VERSION 5.8 ;
BUSBITCHARS "[]" ;
DIVIDERCHAR "/" ;
UNITS
    DATABASE MICRONS 1000 ;
END UNITS

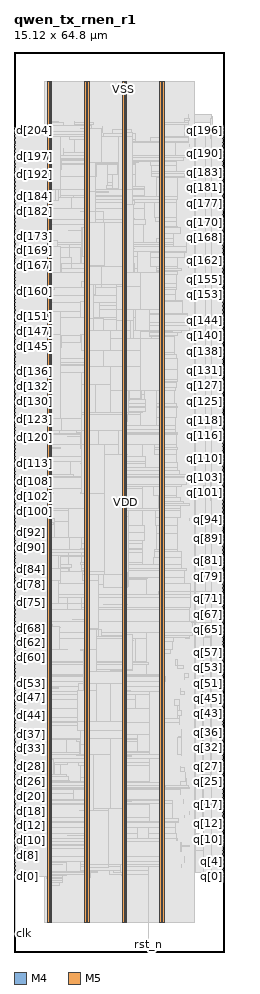
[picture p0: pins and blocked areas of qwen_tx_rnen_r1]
MACRO qwen_tx_rnen_r1
  FOREIGN qwen_tx_rnen_r1 0 0 ;
  CLASS BLOCK ;
  SIZE 15.12 BY 64.8 ;
  PIN clk
    DIRECTION INPUT ;
    USE SIGNAL ;
    PORT
      LAYER M4 ;
        RECT  0.054 1.296 0.138 1.32 ;
    END
    PORT
      LAYER M4 ;
        RECT  0.108 1.296 0.227 1.416 ;
    END
  END clk
  PIN d[0]
    DIRECTION INPUT ;
    USE SIGNAL ;
    PORT
      LAYER M4 ;
        RECT  0.054 5.424 0.138 5.448 ;
    END
  END d[0]
  PIN d[100]
    DIRECTION INPUT ;
    USE SIGNAL ;
    PORT
      LAYER M4 ;
        RECT  0.054 31.728 0.138 31.752 ;
    END
  END d[100]
  PIN d[101]
    DIRECTION INPUT ;
    USE SIGNAL ;
    PORT
      LAYER M4 ;
        RECT  0.054 32.016 0.138 32.04 ;
    END
  END d[101]
  PIN d[102]
    DIRECTION INPUT ;
    USE SIGNAL ;
    PORT
      LAYER M4 ;
        RECT  0.054 32.256 0.138 32.28 ;
    END
  END d[102]
  PIN d[103]
    DIRECTION INPUT ;
    USE SIGNAL ;
    PORT
      LAYER M4 ;
        RECT  0.054 32.496 0.138 32.52 ;
    END
  END d[103]
  PIN d[104]
    DIRECTION INPUT ;
    USE SIGNAL ;
    PORT
      LAYER M4 ;
        RECT  0.054 32.784 0.138 32.808 ;
    END
  END d[104]
  PIN d[105]
    DIRECTION INPUT ;
    USE SIGNAL ;
    PORT
      LAYER M4 ;
        RECT  0.054 33.024 0.138 33.048 ;
    END
  END d[105]
  PIN d[106]
    DIRECTION INPUT ;
    USE SIGNAL ;
    PORT
      LAYER M4 ;
        RECT  0.054 33.312 0.138 33.336 ;
    END
  END d[106]
  PIN d[107]
    DIRECTION INPUT ;
    USE SIGNAL ;
    PORT
      LAYER M4 ;
        RECT  0.054 33.552 0.138 33.576 ;
    END
  END d[107]
  PIN d[108]
    DIRECTION INPUT ;
    USE SIGNAL ;
    PORT
      LAYER M4 ;
        RECT  0.054 33.84 0.138 33.864 ;
    END
  END d[108]
  PIN d[109]
    DIRECTION INPUT ;
    USE SIGNAL ;
    PORT
      LAYER M4 ;
        RECT  0.054 34.08 0.138 34.104 ;
    END
  END d[109]
  PIN d[10]
    DIRECTION INPUT ;
    USE SIGNAL ;
    PORT
      LAYER M4 ;
        RECT  0.054 8.016 0.138 8.04 ;
    END
  END d[10]
  PIN d[110]
    DIRECTION INPUT ;
    USE SIGNAL ;
    PORT
      LAYER M4 ;
        RECT  0.054 34.368 0.138 34.392 ;
    END
  END d[110]
  PIN d[111]
    DIRECTION INPUT ;
    USE SIGNAL ;
    PORT
      LAYER M4 ;
        RECT  0.054 34.608 0.138 34.632 ;
    END
  END d[111]
  PIN d[112]
    DIRECTION INPUT ;
    USE SIGNAL ;
    PORT
      LAYER M4 ;
        RECT  0.054 34.896 0.138 34.92 ;
    END
  END d[112]
  PIN d[113]
    DIRECTION INPUT ;
    USE SIGNAL ;
    PORT
      LAYER M4 ;
        RECT  0.054 35.136 0.138 35.16 ;
    END
  END d[113]
  PIN d[114]
    DIRECTION INPUT ;
    USE SIGNAL ;
    PORT
      LAYER M4 ;
        RECT  0.054 35.424 0.138 35.448 ;
    END
  END d[114]
  PIN d[115]
    DIRECTION INPUT ;
    USE SIGNAL ;
    PORT
      LAYER M4 ;
        RECT  0.054 35.664 0.138 35.688 ;
    END
  END d[115]
  PIN d[116]
    DIRECTION INPUT ;
    USE SIGNAL ;
    PORT
      LAYER M4 ;
        RECT  0.054 35.952 0.138 35.976 ;
    END
  END d[116]
  PIN d[117]
    DIRECTION INPUT ;
    USE SIGNAL ;
    PORT
      LAYER M4 ;
        RECT  0.054 36.192 0.138 36.216 ;
    END
  END d[117]
  PIN d[118]
    DIRECTION INPUT ;
    USE SIGNAL ;
    PORT
      LAYER M4 ;
        RECT  0.054 36.48 0.138 36.504 ;
    END
  END d[118]
  PIN d[119]
    DIRECTION INPUT ;
    USE SIGNAL ;
    PORT
      LAYER M4 ;
        RECT  0.054 36.72 0.138 36.744 ;
    END
  END d[119]
  PIN d[11]
    DIRECTION INPUT ;
    USE SIGNAL ;
    PORT
      LAYER M4 ;
        RECT  0.054 8.304 0.138 8.328 ;
    END
  END d[11]
  PIN d[120]
    DIRECTION INPUT ;
    USE SIGNAL ;
    PORT
      LAYER M4 ;
        RECT  0.054 37.008 0.138 37.032 ;
    END
  END d[120]
  PIN d[121]
    DIRECTION INPUT ;
    USE SIGNAL ;
    PORT
      LAYER M4 ;
        RECT  0.054 37.248 0.138 37.272 ;
    END
  END d[121]
  PIN d[122]
    DIRECTION INPUT ;
    USE SIGNAL ;
    PORT
      LAYER M4 ;
        RECT  0.054 37.536 0.138 37.56 ;
    END
  END d[122]
  PIN d[123]
    DIRECTION INPUT ;
    USE SIGNAL ;
    PORT
      LAYER M4 ;
        RECT  0.054 37.776 0.138 37.8 ;
    END
  END d[123]
  PIN d[124]
    DIRECTION INPUT ;
    USE SIGNAL ;
    PORT
      LAYER M4 ;
        RECT  0.054 38.064 0.138 38.088 ;
    END
  END d[124]
  PIN d[125]
    DIRECTION INPUT ;
    USE SIGNAL ;
    PORT
      LAYER M4 ;
        RECT  0.054 38.304 0.138 38.328 ;
    END
  END d[125]
  PIN d[126]
    DIRECTION INPUT ;
    USE SIGNAL ;
    PORT
      LAYER M4 ;
        RECT  0.054 38.592 0.138 38.616 ;
    END
  END d[126]
  PIN d[127]
    DIRECTION INPUT ;
    USE SIGNAL ;
    PORT
      LAYER M4 ;
        RECT  0.054 38.832 0.138 38.856 ;
    END
  END d[127]
  PIN d[128]
    DIRECTION INPUT ;
    USE SIGNAL ;
    PORT
      LAYER M4 ;
        RECT  0.054 39.12 0.138 39.144 ;
    END
  END d[128]
  PIN d[129]
    DIRECTION INPUT ;
    USE SIGNAL ;
    PORT
      LAYER M4 ;
        RECT  0.054 39.36 0.138 39.384 ;
    END
  END d[129]
  PIN d[12]
    DIRECTION INPUT ;
    USE SIGNAL ;
    PORT
      LAYER M4 ;
        RECT  0.054 8.544 0.138 8.568 ;
    END
  END d[12]
  PIN d[130]
    DIRECTION INPUT ;
    USE SIGNAL ;
    PORT
      LAYER M4 ;
        RECT  0.054 39.648 0.138 39.672 ;
    END
  END d[130]
  PIN d[131]
    DIRECTION INPUT ;
    USE SIGNAL ;
    PORT
      LAYER M4 ;
        RECT  0.054 39.888 0.138 39.912 ;
    END
  END d[131]
  PIN d[132]
    DIRECTION INPUT ;
    USE SIGNAL ;
    PORT
      LAYER M4 ;
        RECT  0.054 40.176 0.138 40.2 ;
    END
  END d[132]
  PIN d[133]
    DIRECTION INPUT ;
    USE SIGNAL ;
    PORT
      LAYER M4 ;
        RECT  0.054 40.416 0.138 40.44 ;
    END
  END d[133]
  PIN d[134]
    DIRECTION INPUT ;
    USE SIGNAL ;
    PORT
      LAYER M4 ;
        RECT  0.054 40.704 0.138 40.728 ;
    END
  END d[134]
  PIN d[135]
    DIRECTION INPUT ;
    USE SIGNAL ;
    PORT
      LAYER M4 ;
        RECT  0.054 40.944 0.138 40.968 ;
    END
  END d[135]
  PIN d[136]
    DIRECTION INPUT ;
    USE SIGNAL ;
    PORT
      LAYER M4 ;
        RECT  0.054 41.232 0.138 41.256 ;
    END
  END d[136]
  PIN d[137]
    DIRECTION INPUT ;
    USE SIGNAL ;
    PORT
      LAYER M4 ;
        RECT  0.054 41.472 0.138 41.496 ;
    END
  END d[137]
  PIN d[138]
    DIRECTION INPUT ;
    USE SIGNAL ;
    PORT
      LAYER M4 ;
        RECT  0.054 41.76 0.138 41.784 ;
    END
  END d[138]
  PIN d[139]
    DIRECTION INPUT ;
    USE SIGNAL ;
    PORT
      LAYER M4 ;
        RECT  0.054 42 0.138 42.024 ;
    END
  END d[139]
  PIN d[13]
    DIRECTION INPUT ;
    USE SIGNAL ;
    PORT
      LAYER M4 ;
        RECT  0.054 8.832 0.138 8.856 ;
    END
  END d[13]
  PIN d[140]
    DIRECTION INPUT ;
    USE SIGNAL ;
    PORT
      LAYER M4 ;
        RECT  0.054 42.288 0.138 42.312 ;
    END
  END d[140]
  PIN d[141]
    DIRECTION INPUT ;
    USE SIGNAL ;
    PORT
      LAYER M4 ;
        RECT  0.054 42.528 0.138 42.552 ;
    END
  END d[141]
  PIN d[142]
    DIRECTION INPUT ;
    USE SIGNAL ;
    PORT
      LAYER M4 ;
        RECT  0.054 42.816 0.138 42.84 ;
    END
  END d[142]
  PIN d[143]
    DIRECTION INPUT ;
    USE SIGNAL ;
    PORT
      LAYER M4 ;
        RECT  0.054 43.056 0.138 43.08 ;
    END
  END d[143]
  PIN d[144]
    DIRECTION INPUT ;
    USE SIGNAL ;
    PORT
      LAYER M4 ;
        RECT  0.054 43.296 0.138 43.32 ;
    END
  END d[144]
  PIN d[145]
    DIRECTION INPUT ;
    USE SIGNAL ;
    PORT
      LAYER M4 ;
        RECT  0.054 43.584 0.138 43.608 ;
    END
  END d[145]
  PIN d[146]
    DIRECTION INPUT ;
    USE SIGNAL ;
    PORT
      LAYER M4 ;
        RECT  0.054 43.824 0.138 43.848 ;
    END
  END d[146]
  PIN d[147]
    DIRECTION INPUT ;
    USE SIGNAL ;
    PORT
      LAYER M4 ;
        RECT  0.054 44.112 0.138 44.136 ;
    END
  END d[147]
  PIN d[148]
    DIRECTION INPUT ;
    USE SIGNAL ;
    PORT
      LAYER M4 ;
        RECT  0.054 44.352 0.138 44.376 ;
    END
  END d[148]
  PIN d[149]
    DIRECTION INPUT ;
    USE SIGNAL ;
    PORT
      LAYER M4 ;
        RECT  0.054 44.64 0.138 44.664 ;
    END
  END d[149]
  PIN d[14]
    DIRECTION INPUT ;
    USE SIGNAL ;
    PORT
      LAYER M4 ;
        RECT  0.054 9.072 0.138 9.096 ;
    END
  END d[14]
  PIN d[150]
    DIRECTION INPUT ;
    USE SIGNAL ;
    PORT
      LAYER M4 ;
        RECT  0.054 44.88 0.138 44.904 ;
    END
  END d[150]
  PIN d[151]
    DIRECTION INPUT ;
    USE SIGNAL ;
    PORT
      LAYER M4 ;
        RECT  0.054 45.168 0.138 45.192 ;
    END
  END d[151]
  PIN d[152]
    DIRECTION INPUT ;
    USE SIGNAL ;
    PORT
      LAYER M4 ;
        RECT  0.054 45.408 0.138 45.432 ;
    END
  END d[152]
  PIN d[153]
    DIRECTION INPUT ;
    USE SIGNAL ;
    PORT
      LAYER M4 ;
        RECT  0.054 45.696 0.138 45.72 ;
    END
  END d[153]
  PIN d[154]
    DIRECTION INPUT ;
    USE SIGNAL ;
    PORT
      LAYER M4 ;
        RECT  0.054 45.936 0.138 45.96 ;
    END
  END d[154]
  PIN d[155]
    DIRECTION INPUT ;
    USE SIGNAL ;
    PORT
      LAYER M4 ;
        RECT  0.054 46.224 0.138 46.248 ;
    END
  END d[155]
  PIN d[156]
    DIRECTION INPUT ;
    USE SIGNAL ;
    PORT
      LAYER M4 ;
        RECT  0.054 46.464 0.138 46.488 ;
    END
  END d[156]
  PIN d[157]
    DIRECTION INPUT ;
    USE SIGNAL ;
    PORT
      LAYER M4 ;
        RECT  0.054 46.752 0.138 46.776 ;
    END
  END d[157]
  PIN d[158]
    DIRECTION INPUT ;
    USE SIGNAL ;
    PORT
      LAYER M4 ;
        RECT  0.054 46.992 0.138 47.016 ;
    END
  END d[158]
  PIN d[159]
    DIRECTION INPUT ;
    USE SIGNAL ;
    PORT
      LAYER M4 ;
        RECT  0.054 47.28 0.138 47.304 ;
    END
  END d[159]
  PIN d[15]
    DIRECTION INPUT ;
    USE SIGNAL ;
    PORT
      LAYER M4 ;
        RECT  0.054 9.36 0.138 9.384 ;
    END
  END d[15]
  PIN d[160]
    DIRECTION INPUT ;
    USE SIGNAL ;
    PORT
      LAYER M4 ;
        RECT  0.054 47.52 0.138 47.544 ;
    END
  END d[160]
  PIN d[161]
    DIRECTION INPUT ;
    USE SIGNAL ;
    PORT
      LAYER M4 ;
        RECT  0.054 47.808 0.138 47.832 ;
    END
  END d[161]
  PIN d[162]
    DIRECTION INPUT ;
    USE SIGNAL ;
    PORT
      LAYER M4 ;
        RECT  0.054 48.048 0.138 48.072 ;
    END
  END d[162]
  PIN d[163]
    DIRECTION INPUT ;
    USE SIGNAL ;
    PORT
      LAYER M4 ;
        RECT  0.054 48.336 0.138 48.36 ;
    END
  END d[163]
  PIN d[164]
    DIRECTION INPUT ;
    USE SIGNAL ;
    PORT
      LAYER M4 ;
        RECT  0.054 48.576 0.138 48.6 ;
    END
  END d[164]
  PIN d[165]
    DIRECTION INPUT ;
    USE SIGNAL ;
    PORT
      LAYER M4 ;
        RECT  0.054 48.864 0.138 48.888 ;
    END
  END d[165]
  PIN d[166]
    DIRECTION INPUT ;
    USE SIGNAL ;
    PORT
      LAYER M4 ;
        RECT  0.054 49.104 0.138 49.128 ;
    END
  END d[166]
  PIN d[167]
    DIRECTION INPUT ;
    USE SIGNAL ;
    PORT
      LAYER M4 ;
        RECT  0.054 49.392 0.138 49.416 ;
    END
  END d[167]
  PIN d[168]
    DIRECTION INPUT ;
    USE SIGNAL ;
    PORT
      LAYER M4 ;
        RECT  0.054 49.632 0.138 49.656 ;
    END
  END d[168]
  PIN d[169]
    DIRECTION INPUT ;
    USE SIGNAL ;
    PORT
      LAYER M4 ;
        RECT  0.054 49.92 0.138 49.944 ;
    END
  END d[169]
  PIN d[16]
    DIRECTION INPUT ;
    USE SIGNAL ;
    PORT
      LAYER M4 ;
        RECT  0.054 9.6 0.138 9.624 ;
    END
  END d[16]
  PIN d[170]
    DIRECTION INPUT ;
    USE SIGNAL ;
    PORT
      LAYER M4 ;
        RECT  0.054 50.16 0.138 50.184 ;
    END
  END d[170]
  PIN d[171]
    DIRECTION INPUT ;
    USE SIGNAL ;
    PORT
      LAYER M4 ;
        RECT  0.054 50.448 0.138 50.472 ;
    END
  END d[171]
  PIN d[172]
    DIRECTION INPUT ;
    USE SIGNAL ;
    PORT
      LAYER M4 ;
        RECT  0.054 50.688 0.138 50.712 ;
    END
  END d[172]
  PIN d[173]
    DIRECTION INPUT ;
    USE SIGNAL ;
    PORT
      LAYER M4 ;
        RECT  0.054 50.976 0.138 51 ;
    END
  END d[173]
  PIN d[174]
    DIRECTION INPUT ;
    USE SIGNAL ;
    PORT
      LAYER M4 ;
        RECT  0.054 51.216 0.138 51.24 ;
    END
  END d[174]
  PIN d[175]
    DIRECTION INPUT ;
    USE SIGNAL ;
    PORT
      LAYER M4 ;
        RECT  0.054 51.504 0.138 51.528 ;
    END
  END d[175]
  PIN d[176]
    DIRECTION INPUT ;
    USE SIGNAL ;
    PORT
      LAYER M4 ;
        RECT  0.054 51.744 0.138 51.768 ;
    END
  END d[176]
  PIN d[177]
    DIRECTION INPUT ;
    USE SIGNAL ;
    PORT
      LAYER M4 ;
        RECT  0.054 52.032 0.138 52.056 ;
    END
  END d[177]
  PIN d[178]
    DIRECTION INPUT ;
    USE SIGNAL ;
    PORT
      LAYER M4 ;
        RECT  0.054 52.272 0.138 52.296 ;
    END
  END d[178]
  PIN d[179]
    DIRECTION INPUT ;
    USE SIGNAL ;
    PORT
      LAYER M4 ;
        RECT  0.054 52.56 0.138 52.584 ;
    END
  END d[179]
  PIN d[17]
    DIRECTION INPUT ;
    USE SIGNAL ;
    PORT
      LAYER M4 ;
        RECT  0.054 9.888 0.138 9.912 ;
    END
  END d[17]
  PIN d[180]
    DIRECTION INPUT ;
    USE SIGNAL ;
    PORT
      LAYER M4 ;
        RECT  0.054 52.8 0.138 52.824 ;
    END
  END d[180]
  PIN d[181]
    DIRECTION INPUT ;
    USE SIGNAL ;
    PORT
      LAYER M4 ;
        RECT  0.054 53.088 0.138 53.112 ;
    END
  END d[181]
  PIN d[182]
    DIRECTION INPUT ;
    USE SIGNAL ;
    PORT
      LAYER M4 ;
        RECT  0.054 53.328 0.138 53.352 ;
    END
  END d[182]
  PIN d[183]
    DIRECTION INPUT ;
    USE SIGNAL ;
    PORT
      LAYER M4 ;
        RECT  0.054 53.616 0.138 53.64 ;
    END
  END d[183]
  PIN d[184]
    DIRECTION INPUT ;
    USE SIGNAL ;
    PORT
      LAYER M4 ;
        RECT  0.054 53.856 0.138 53.88 ;
    END
  END d[184]
  PIN d[185]
    DIRECTION INPUT ;
    USE SIGNAL ;
    PORT
      LAYER M4 ;
        RECT  0.054 54.096 0.138 54.12 ;
    END
  END d[185]
  PIN d[186]
    DIRECTION INPUT ;
    USE SIGNAL ;
    PORT
      LAYER M4 ;
        RECT  0.054 54.384 0.138 54.408 ;
    END
  END d[186]
  PIN d[187]
    DIRECTION INPUT ;
    USE SIGNAL ;
    PORT
      LAYER M4 ;
        RECT  0.054 54.624 0.138 54.648 ;
    END
  END d[187]
  PIN d[188]
    DIRECTION INPUT ;
    USE SIGNAL ;
    PORT
      LAYER M4 ;
        RECT  0.054 54.912 0.138 54.936 ;
    END
  END d[188]
  PIN d[189]
    DIRECTION INPUT ;
    USE SIGNAL ;
    PORT
      LAYER M4 ;
        RECT  0.054 55.152 0.138 55.176 ;
    END
  END d[189]
  PIN d[18]
    DIRECTION INPUT ;
    USE SIGNAL ;
    PORT
      LAYER M4 ;
        RECT  0.054 10.128 0.138 10.152 ;
    END
  END d[18]
  PIN d[190]
    DIRECTION INPUT ;
    USE SIGNAL ;
    PORT
      LAYER M4 ;
        RECT  0.054 55.44 0.138 55.464 ;
    END
  END d[190]
  PIN d[191]
    DIRECTION INPUT ;
    USE SIGNAL ;
    PORT
      LAYER M4 ;
        RECT  0.054 55.68 0.138 55.704 ;
    END
  END d[191]
  PIN d[192]
    DIRECTION INPUT ;
    USE SIGNAL ;
    PORT
      LAYER M4 ;
        RECT  0.054 55.968 0.138 55.992 ;
    END
  END d[192]
  PIN d[193]
    DIRECTION INPUT ;
    USE SIGNAL ;
    PORT
      LAYER M4 ;
        RECT  0.054 56.208 0.138 56.232 ;
    END
  END d[193]
  PIN d[194]
    DIRECTION INPUT ;
    USE SIGNAL ;
    PORT
      LAYER M4 ;
        RECT  0.054 56.496 0.138 56.52 ;
    END
  END d[194]
  PIN d[195]
    DIRECTION INPUT ;
    USE SIGNAL ;
    PORT
      LAYER M4 ;
        RECT  0.054 56.736 0.138 56.76 ;
    END
  END d[195]
  PIN d[196]
    DIRECTION INPUT ;
    USE SIGNAL ;
    PORT
      LAYER M4 ;
        RECT  0.054 57.024 0.138 57.048 ;
    END
  END d[196]
  PIN d[197]
    DIRECTION INPUT ;
    USE SIGNAL ;
    PORT
      LAYER M4 ;
        RECT  0.054 57.264 0.138 57.288 ;
    END
  END d[197]
  PIN d[198]
    DIRECTION INPUT ;
    USE SIGNAL ;
    PORT
      LAYER M4 ;
        RECT  0.054 57.552 0.138 57.576 ;
    END
  END d[198]
  PIN d[199]
    DIRECTION INPUT ;
    USE SIGNAL ;
    PORT
      LAYER M4 ;
        RECT  0.054 57.792 0.138 57.816 ;
    END
  END d[199]
  PIN d[19]
    DIRECTION INPUT ;
    USE SIGNAL ;
    PORT
      LAYER M4 ;
        RECT  0.054 10.416 0.138 10.44 ;
    END
  END d[19]
  PIN d[1]
    DIRECTION INPUT ;
    USE SIGNAL ;
    PORT
      LAYER M4 ;
        RECT  0.054 5.664 0.138 5.688 ;
    END
  END d[1]
  PIN d[200]
    DIRECTION INPUT ;
    USE SIGNAL ;
    PORT
      LAYER M4 ;
        RECT  0.054 58.08 0.138 58.104 ;
    END
  END d[200]
  PIN d[201]
    DIRECTION INPUT ;
    USE SIGNAL ;
    PORT
      LAYER M4 ;
        RECT  0.054 58.32 0.138 58.344 ;
    END
    PORT
      LAYER M4 ;
        RECT  0.025 58.224 0.108 58.344 ;
    END
  END d[201]
  PIN d[202]
    DIRECTION INPUT ;
    USE SIGNAL ;
    PORT
      LAYER M4 ;
        RECT  0.054 58.608 0.138 58.632 ;
    END
  END d[202]
  PIN d[203]
    DIRECTION INPUT ;
    USE SIGNAL ;
    PORT
      LAYER M4 ;
        RECT  0.054 58.848 0.138 58.872 ;
    END
  END d[203]
  PIN d[204]
    DIRECTION INPUT ;
    USE SIGNAL ;
    PORT
      LAYER M4 ;
        RECT  0.054 59.136 0.138 59.16 ;
    END
  END d[204]
  PIN d[205]
    DIRECTION INPUT ;
    USE SIGNAL ;
    PORT
      LAYER M4 ;
        RECT  0.054 59.376 0.138 59.4 ;
    END
  END d[205]
  PIN d[20]
    DIRECTION INPUT ;
    USE SIGNAL ;
    PORT
      LAYER M4 ;
        RECT  0.054 10.656 0.138 10.68 ;
    END
  END d[20]
  PIN d[21]
    DIRECTION INPUT ;
    USE SIGNAL ;
    PORT
      LAYER M4 ;
        RECT  0.054 10.896 0.138 10.92 ;
    END
  END d[21]
  PIN d[22]
    DIRECTION INPUT ;
    USE SIGNAL ;
    PORT
      LAYER M4 ;
        RECT  0.054 11.184 0.138 11.208 ;
    END
  END d[22]
  PIN d[23]
    DIRECTION INPUT ;
    USE SIGNAL ;
    PORT
      LAYER M4 ;
        RECT  0.054 11.424 0.138 11.448 ;
    END
  END d[23]
  PIN d[24]
    DIRECTION INPUT ;
    USE SIGNAL ;
    PORT
      LAYER M4 ;
        RECT  0.054 11.712 0.138 11.736 ;
    END
  END d[24]
  PIN d[25]
    DIRECTION INPUT ;
    USE SIGNAL ;
    PORT
      LAYER M4 ;
        RECT  0.054 11.952 0.138 11.976 ;
    END
  END d[25]
  PIN d[26]
    DIRECTION INPUT ;
    USE SIGNAL ;
    PORT
      LAYER M4 ;
        RECT  0.054 12.24 0.138 12.264 ;
    END
  END d[26]
  PIN d[27]
    DIRECTION INPUT ;
    USE SIGNAL ;
    PORT
      LAYER M4 ;
        RECT  0.054 12.48 0.138 12.504 ;
    END
  END d[27]
  PIN d[28]
    DIRECTION INPUT ;
    USE SIGNAL ;
    PORT
      LAYER M4 ;
        RECT  0.054 12.768 0.138 12.792 ;
    END
  END d[28]
  PIN d[29]
    DIRECTION INPUT ;
    USE SIGNAL ;
    PORT
      LAYER M4 ;
        RECT  0.054 13.008 0.138 13.032 ;
    END
  END d[29]
  PIN d[2]
    DIRECTION INPUT ;
    USE SIGNAL ;
    PORT
      LAYER M4 ;
        RECT  0.054 5.904 0.138 5.928 ;
    END
  END d[2]
  PIN d[30]
    DIRECTION INPUT ;
    USE SIGNAL ;
    PORT
      LAYER M4 ;
        RECT  0.054 13.296 0.138 13.32 ;
    END
  END d[30]
  PIN d[31]
    DIRECTION INPUT ;
    USE SIGNAL ;
    PORT
      LAYER M4 ;
        RECT  0.054 13.536 0.138 13.56 ;
    END
  END d[31]
  PIN d[32]
    DIRECTION INPUT ;
    USE SIGNAL ;
    PORT
      LAYER M4 ;
        RECT  0.054 13.824 0.138 13.848 ;
    END
  END d[32]
  PIN d[33]
    DIRECTION INPUT ;
    USE SIGNAL ;
    PORT
      LAYER M4 ;
        RECT  0.054 14.064 0.138 14.088 ;
    END
  END d[33]
  PIN d[34]
    DIRECTION INPUT ;
    USE SIGNAL ;
    PORT
      LAYER M4 ;
        RECT  0.054 14.352 0.138 14.376 ;
    END
  END d[34]
  PIN d[35]
    DIRECTION INPUT ;
    USE SIGNAL ;
    PORT
      LAYER M4 ;
        RECT  0.054 14.592 0.138 14.616 ;
    END
  END d[35]
  PIN d[36]
    DIRECTION INPUT ;
    USE SIGNAL ;
    PORT
      LAYER M4 ;
        RECT  0.054 14.88 0.138 14.904 ;
    END
  END d[36]
  PIN d[37]
    DIRECTION INPUT ;
    USE SIGNAL ;
    PORT
      LAYER M4 ;
        RECT  0.054 15.12 0.138 15.144 ;
    END
  END d[37]
  PIN d[38]
    DIRECTION INPUT ;
    USE SIGNAL ;
    PORT
      LAYER M4 ;
        RECT  0.054 15.408 0.138 15.432 ;
    END
  END d[38]
  PIN d[39]
    DIRECTION INPUT ;
    USE SIGNAL ;
    PORT
      LAYER M4 ;
        RECT  0.054 15.648 0.138 15.672 ;
    END
  END d[39]
  PIN d[3]
    DIRECTION INPUT ;
    USE SIGNAL ;
    PORT
      LAYER M4 ;
        RECT  0.054 6.192 0.138 6.216 ;
    END
  END d[3]
  PIN d[40]
    DIRECTION INPUT ;
    USE SIGNAL ;
    PORT
      LAYER M4 ;
        RECT  0.054 15.936 0.138 15.96 ;
    END
  END d[40]
  PIN d[41]
    DIRECTION INPUT ;
    USE SIGNAL ;
    PORT
      LAYER M4 ;
        RECT  0.054 16.176 0.138 16.2 ;
    END
  END d[41]
  PIN d[42]
    DIRECTION INPUT ;
    USE SIGNAL ;
    PORT
      LAYER M4 ;
        RECT  0.054 16.464 0.138 16.488 ;
    END
  END d[42]
  PIN d[43]
    DIRECTION INPUT ;
    USE SIGNAL ;
    PORT
      LAYER M4 ;
        RECT  0.054 16.704 0.138 16.728 ;
    END
  END d[43]
  PIN d[44]
    DIRECTION INPUT ;
    USE SIGNAL ;
    PORT
      LAYER M4 ;
        RECT  0.054 16.992 0.138 17.016 ;
    END
  END d[44]
  PIN d[45]
    DIRECTION INPUT ;
    USE SIGNAL ;
    PORT
      LAYER M4 ;
        RECT  0.054 17.232 0.138 17.256 ;
    END
  END d[45]
  PIN d[46]
    DIRECTION INPUT ;
    USE SIGNAL ;
    PORT
      LAYER M4 ;
        RECT  0.054 17.52 0.138 17.544 ;
    END
  END d[46]
  PIN d[47]
    DIRECTION INPUT ;
    USE SIGNAL ;
    PORT
      LAYER M4 ;
        RECT  0.054 17.76 0.138 17.784 ;
    END
  END d[47]
  PIN d[48]
    DIRECTION INPUT ;
    USE SIGNAL ;
    PORT
      LAYER M4 ;
        RECT  0.054 18.048 0.138 18.072 ;
    END
  END d[48]
  PIN d[49]
    DIRECTION INPUT ;
    USE SIGNAL ;
    PORT
      LAYER M4 ;
        RECT  0.054 18.288 0.138 18.312 ;
    END
  END d[49]
  PIN d[4]
    DIRECTION INPUT ;
    USE SIGNAL ;
    PORT
      LAYER M4 ;
        RECT  0.054 6.432 0.138 6.456 ;
    END
  END d[4]
  PIN d[50]
    DIRECTION INPUT ;
    USE SIGNAL ;
    PORT
      LAYER M4 ;
        RECT  0.054 18.576 0.138 18.6 ;
    END
  END d[50]
  PIN d[51]
    DIRECTION INPUT ;
    USE SIGNAL ;
    PORT
      LAYER M4 ;
        RECT  0.054 18.816 0.138 18.84 ;
    END
  END d[51]
  PIN d[52]
    DIRECTION INPUT ;
    USE SIGNAL ;
    PORT
      LAYER M4 ;
        RECT  0.054 19.104 0.138 19.128 ;
    END
  END d[52]
  PIN d[53]
    DIRECTION INPUT ;
    USE SIGNAL ;
    PORT
      LAYER M4 ;
        RECT  0.054 19.344 0.138 19.368 ;
    END
  END d[53]
  PIN d[54]
    DIRECTION INPUT ;
    USE SIGNAL ;
    PORT
      LAYER M4 ;
        RECT  0.054 19.632 0.138 19.656 ;
    END
  END d[54]
  PIN d[55]
    DIRECTION INPUT ;
    USE SIGNAL ;
    PORT
      LAYER M4 ;
        RECT  0.054 19.872 0.138 19.896 ;
    END
  END d[55]
  PIN d[56]
    DIRECTION INPUT ;
    USE SIGNAL ;
    PORT
      LAYER M4 ;
        RECT  0.054 20.16 0.138 20.184 ;
    END
  END d[56]
  PIN d[57]
    DIRECTION INPUT ;
    USE SIGNAL ;
    PORT
      LAYER M4 ;
        RECT  0.054 20.4 0.138 20.424 ;
    END
  END d[57]
  PIN d[58]
    DIRECTION INPUT ;
    USE SIGNAL ;
    PORT
      LAYER M4 ;
        RECT  0.054 20.688 0.138 20.712 ;
    END
  END d[58]
  PIN d[59]
    DIRECTION INPUT ;
    USE SIGNAL ;
    PORT
      LAYER M4 ;
        RECT  0.054 20.928 0.138 20.952 ;
    END
  END d[59]
  PIN d[5]
    DIRECTION INPUT ;
    USE SIGNAL ;
    PORT
      LAYER M4 ;
        RECT  0.054 6.72 0.138 6.744 ;
    END
  END d[5]
  PIN d[60]
    DIRECTION INPUT ;
    USE SIGNAL ;
    PORT
      LAYER M4 ;
        RECT  0.054 21.216 0.138 21.24 ;
    END
  END d[60]
  PIN d[61]
    DIRECTION INPUT ;
    USE SIGNAL ;
    PORT
      LAYER M4 ;
        RECT  0.054 21.456 0.138 21.48 ;
    END
  END d[61]
  PIN d[62]
    DIRECTION INPUT ;
    USE SIGNAL ;
    PORT
      LAYER M4 ;
        RECT  0.054 21.696 0.138 21.72 ;
    END
  END d[62]
  PIN d[63]
    DIRECTION INPUT ;
    USE SIGNAL ;
    PORT
      LAYER M4 ;
        RECT  0.054 21.984 0.138 22.008 ;
    END
  END d[63]
  PIN d[64]
    DIRECTION INPUT ;
    USE SIGNAL ;
    PORT
      LAYER M4 ;
        RECT  0.054 22.224 0.138 22.248 ;
    END
  END d[64]
  PIN d[65]
    DIRECTION INPUT ;
    USE SIGNAL ;
    PORT
      LAYER M4 ;
        RECT  0.054 22.512 0.138 22.536 ;
    END
  END d[65]
  PIN d[66]
    DIRECTION INPUT ;
    USE SIGNAL ;
    PORT
      LAYER M4 ;
        RECT  0.054 22.752 0.138 22.776 ;
    END
  END d[66]
  PIN d[67]
    DIRECTION INPUT ;
    USE SIGNAL ;
    PORT
      LAYER M4 ;
        RECT  0.054 23.04 0.138 23.064 ;
    END
  END d[67]
  PIN d[68]
    DIRECTION INPUT ;
    USE SIGNAL ;
    PORT
      LAYER M4 ;
        RECT  0.054 23.28 0.138 23.304 ;
    END
  END d[68]
  PIN d[69]
    DIRECTION INPUT ;
    USE SIGNAL ;
    PORT
      LAYER M4 ;
        RECT  0.054 23.568 0.138 23.592 ;
    END
  END d[69]
  PIN d[6]
    DIRECTION INPUT ;
    USE SIGNAL ;
    PORT
      LAYER M4 ;
        RECT  0.054 6.96 0.138 6.984 ;
    END
  END d[6]
  PIN d[70]
    DIRECTION INPUT ;
    USE SIGNAL ;
    PORT
      LAYER M4 ;
        RECT  0.054 23.808 0.138 23.832 ;
    END
  END d[70]
  PIN d[71]
    DIRECTION INPUT ;
    USE SIGNAL ;
    PORT
      LAYER M4 ;
        RECT  0.054 24.096 0.138 24.12 ;
    END
  END d[71]
  PIN d[72]
    DIRECTION INPUT ;
    USE SIGNAL ;
    PORT
      LAYER M4 ;
        RECT  0.054 24.336 0.138 24.36 ;
    END
  END d[72]
  PIN d[73]
    DIRECTION INPUT ;
    USE SIGNAL ;
    PORT
      LAYER M4 ;
        RECT  0.054 24.624 0.138 24.648 ;
    END
  END d[73]
  PIN d[74]
    DIRECTION INPUT ;
    USE SIGNAL ;
    PORT
      LAYER M4 ;
        RECT  0.054 24.864 0.138 24.888 ;
    END
  END d[74]
  PIN d[75]
    DIRECTION INPUT ;
    USE SIGNAL ;
    PORT
      LAYER M4 ;
        RECT  0.054 25.152 0.138 25.176 ;
    END
  END d[75]
  PIN d[76]
    DIRECTION INPUT ;
    USE SIGNAL ;
    PORT
      LAYER M4 ;
        RECT  0.054 25.392 0.138 25.416 ;
    END
  END d[76]
  PIN d[77]
    DIRECTION INPUT ;
    USE SIGNAL ;
    PORT
      LAYER M4 ;
        RECT  0.054 25.68 0.138 25.704 ;
    END
  END d[77]
  PIN d[78]
    DIRECTION INPUT ;
    USE SIGNAL ;
    PORT
      LAYER M4 ;
        RECT  0.054 25.92 0.138 25.944 ;
    END
  END d[78]
  PIN d[79]
    DIRECTION INPUT ;
    USE SIGNAL ;
    PORT
      LAYER M4 ;
        RECT  0.054 26.208 0.138 26.232 ;
    END
  END d[79]
  PIN d[7]
    DIRECTION INPUT ;
    USE SIGNAL ;
    PORT
      LAYER M4 ;
        RECT  0.054 7.248 0.138 7.272 ;
    END
  END d[7]
  PIN d[80]
    DIRECTION INPUT ;
    USE SIGNAL ;
    PORT
      LAYER M4 ;
        RECT  0.054 26.448 0.138 26.472 ;
    END
  END d[80]
  PIN d[81]
    DIRECTION INPUT ;
    USE SIGNAL ;
    PORT
      LAYER M4 ;
        RECT  0.054 26.736 0.138 26.76 ;
    END
  END d[81]
  PIN d[82]
    DIRECTION INPUT ;
    USE SIGNAL ;
    PORT
      LAYER M4 ;
        RECT  0.054 26.976 0.138 27 ;
    END
  END d[82]
  PIN d[83]
    DIRECTION INPUT ;
    USE SIGNAL ;
    PORT
      LAYER M4 ;
        RECT  0.054 27.264 0.138 27.288 ;
    END
  END d[83]
  PIN d[84]
    DIRECTION INPUT ;
    USE SIGNAL ;
    PORT
      LAYER M4 ;
        RECT  0.054 27.504 0.138 27.528 ;
    END
  END d[84]
  PIN d[85]
    DIRECTION INPUT ;
    USE SIGNAL ;
    PORT
      LAYER M4 ;
        RECT  0.054 27.792 0.138 27.816 ;
    END
  END d[85]
  PIN d[86]
    DIRECTION INPUT ;
    USE SIGNAL ;
    PORT
      LAYER M4 ;
        RECT  0.054 28.032 0.138 28.056 ;
    END
  END d[86]
  PIN d[87]
    DIRECTION INPUT ;
    USE SIGNAL ;
    PORT
      LAYER M4 ;
        RECT  0.054 28.32 0.138 28.344 ;
    END
  END d[87]
  PIN d[88]
    DIRECTION INPUT ;
    USE SIGNAL ;
    PORT
      LAYER M4 ;
        RECT  0.054 28.56 0.138 28.584 ;
    END
  END d[88]
  PIN d[89]
    DIRECTION INPUT ;
    USE SIGNAL ;
    PORT
      LAYER M4 ;
        RECT  0.054 28.848 0.138 28.872 ;
    END
  END d[89]
  PIN d[8]
    DIRECTION INPUT ;
    USE SIGNAL ;
    PORT
      LAYER M4 ;
        RECT  0.054 7.488 0.138 7.512 ;
    END
  END d[8]
  PIN d[90]
    DIRECTION INPUT ;
    USE SIGNAL ;
    PORT
      LAYER M4 ;
        RECT  0.054 29.088 0.138 29.112 ;
    END
  END d[90]
  PIN d[91]
    DIRECTION INPUT ;
    USE SIGNAL ;
    PORT
      LAYER M4 ;
        RECT  0.054 29.376 0.138 29.4 ;
    END
  END d[91]
  PIN d[92]
    DIRECTION INPUT ;
    USE SIGNAL ;
    PORT
      LAYER M4 ;
        RECT  0.054 29.616 0.138 29.64 ;
    END
  END d[92]
  PIN d[93]
    DIRECTION INPUT ;
    USE SIGNAL ;
    PORT
      LAYER M4 ;
        RECT  0.054 29.904 0.138 29.928 ;
    END
  END d[93]
  PIN d[94]
    DIRECTION INPUT ;
    USE SIGNAL ;
    PORT
      LAYER M4 ;
        RECT  0.054 30.144 0.138 30.168 ;
    END
  END d[94]
  PIN d[95]
    DIRECTION INPUT ;
    USE SIGNAL ;
    PORT
      LAYER M4 ;
        RECT  0.054 30.432 0.138 30.456 ;
    END
  END d[95]
  PIN d[96]
    DIRECTION INPUT ;
    USE SIGNAL ;
    PORT
      LAYER M4 ;
        RECT  0.054 30.672 0.138 30.696 ;
    END
  END d[96]
  PIN d[97]
    DIRECTION INPUT ;
    USE SIGNAL ;
    PORT
      LAYER M4 ;
        RECT  0.054 30.96 0.138 30.984 ;
    END
  END d[97]
  PIN d[98]
    DIRECTION INPUT ;
    USE SIGNAL ;
    PORT
      LAYER M4 ;
        RECT  0.054 31.2 0.138 31.224 ;
    END
  END d[98]
  PIN d[99]
    DIRECTION INPUT ;
    USE SIGNAL ;
    PORT
      LAYER M4 ;
        RECT  0.054 31.488 0.138 31.512 ;
    END
  END d[99]
  PIN d[9]
    DIRECTION INPUT ;
    USE SIGNAL ;
    PORT
      LAYER M4 ;
        RECT  0.054 7.776 0.138 7.8 ;
    END
  END d[9]
  PIN q[0]
    DIRECTION OUTPUT ;
    USE SIGNAL ;
    PORT
      LAYER M4 ;
        RECT  14.982 5.424 15.066 5.448 ;
    END
  END q[0]
  PIN q[100]
    DIRECTION OUTPUT ;
    USE SIGNAL ;
    PORT
      LAYER M4 ;
        RECT  14.982 32.784 15.066 32.808 ;
    END
  END q[100]
  PIN q[101]
    DIRECTION OUTPUT ;
    USE SIGNAL ;
    PORT
      LAYER M4 ;
        RECT  14.982 33.072 15.066 33.096 ;
    END
  END q[101]
  PIN q[102]
    DIRECTION OUTPUT ;
    USE SIGNAL ;
    PORT
      LAYER M4 ;
        RECT  14.982 33.36 15.066 33.384 ;
    END
  END q[102]
  PIN q[103]
    DIRECTION OUTPUT ;
    USE SIGNAL ;
    PORT
      LAYER M4 ;
        RECT  14.982 33.6 15.066 33.624 ;
    END
  END q[103]
  PIN q[104]
    DIRECTION OUTPUT ;
    USE SIGNAL ;
    PORT
      LAYER M4 ;
        RECT  14.982 33.888 15.066 33.912 ;
    END
  END q[104]
  PIN q[105]
    DIRECTION OUTPUT ;
    USE SIGNAL ;
    PORT
      LAYER M4 ;
        RECT  14.982 34.176 15.066 34.2 ;
    END
  END q[105]
  PIN q[106]
    DIRECTION OUTPUT ;
    USE SIGNAL ;
    PORT
      LAYER M4 ;
        RECT  14.982 34.464 15.066 34.488 ;
    END
  END q[106]
  PIN q[107]
    DIRECTION OUTPUT ;
    USE SIGNAL ;
    PORT
      LAYER M4 ;
        RECT  14.982 34.704 15.066 34.728 ;
    END
  END q[107]
  PIN q[108]
    DIRECTION OUTPUT ;
    USE SIGNAL ;
    PORT
      LAYER M4 ;
        RECT  14.982 34.992 15.066 35.016 ;
    END
  END q[108]
  PIN q[109]
    DIRECTION OUTPUT ;
    USE SIGNAL ;
    PORT
      LAYER M4 ;
        RECT  14.982 35.28 15.066 35.304 ;
    END
  END q[109]
  PIN q[10]
    DIRECTION OUTPUT ;
    USE SIGNAL ;
    PORT
      LAYER M4 ;
        RECT  14.982 8.112 15.066 8.136 ;
    END
  END q[10]
  PIN q[110]
    DIRECTION OUTPUT ;
    USE SIGNAL ;
    PORT
      LAYER M4 ;
        RECT  14.982 35.52 15.066 35.544 ;
    END
  END q[110]
  PIN q[111]
    DIRECTION OUTPUT ;
    USE SIGNAL ;
    PORT
      LAYER M4 ;
        RECT  14.982 35.808 15.066 35.832 ;
    END
  END q[111]
  PIN q[112]
    DIRECTION OUTPUT ;
    USE SIGNAL ;
    PORT
      LAYER M4 ;
        RECT  14.982 36.096 15.066 36.12 ;
    END
  END q[112]
  PIN q[113]
    DIRECTION OUTPUT ;
    USE SIGNAL ;
    PORT
      LAYER M4 ;
        RECT  14.982 36.384 15.066 36.408 ;
    END
  END q[113]
  PIN q[114]
    DIRECTION OUTPUT ;
    USE SIGNAL ;
    PORT
      LAYER M4 ;
        RECT  14.982 36.624 15.066 36.648 ;
    END
  END q[114]
  PIN q[115]
    DIRECTION OUTPUT ;
    USE SIGNAL ;
    PORT
      LAYER M4 ;
        RECT  14.982 36.912 15.066 36.936 ;
    END
  END q[115]
  PIN q[116]
    DIRECTION OUTPUT ;
    USE SIGNAL ;
    PORT
      LAYER M4 ;
        RECT  14.982 37.2 15.066 37.224 ;
    END
  END q[116]
  PIN q[117]
    DIRECTION OUTPUT ;
    USE SIGNAL ;
    PORT
      LAYER M4 ;
        RECT  14.982 37.44 15.066 37.464 ;
    END
  END q[117]
  PIN q[118]
    DIRECTION OUTPUT ;
    USE SIGNAL ;
    PORT
      LAYER M4 ;
        RECT  14.982 37.728 15.066 37.752 ;
    END
  END q[118]
  PIN q[119]
    DIRECTION OUTPUT ;
    USE SIGNAL ;
    PORT
      LAYER M4 ;
        RECT  14.982 38.016 15.066 38.04 ;
    END
  END q[119]
  PIN q[11]
    DIRECTION OUTPUT ;
    USE SIGNAL ;
    PORT
      LAYER M4 ;
        RECT  14.982 8.4 15.066 8.424 ;
    END
  END q[11]
  PIN q[120]
    DIRECTION OUTPUT ;
    USE SIGNAL ;
    PORT
      LAYER M4 ;
        RECT  14.982 38.304 15.066 38.328 ;
    END
  END q[120]
  PIN q[121]
    DIRECTION OUTPUT ;
    USE SIGNAL ;
    PORT
      LAYER M4 ;
        RECT  14.982 38.544 15.066 38.568 ;
    END
  END q[121]
  PIN q[122]
    DIRECTION OUTPUT ;
    USE SIGNAL ;
    PORT
      LAYER M4 ;
        RECT  14.982 38.832 15.066 38.856 ;
    END
  END q[122]
  PIN q[123]
    DIRECTION OUTPUT ;
    USE SIGNAL ;
    PORT
      LAYER M4 ;
        RECT  14.982 39.12 15.066 39.144 ;
    END
  END q[123]
  PIN q[124]
    DIRECTION OUTPUT ;
    USE SIGNAL ;
    PORT
      LAYER M4 ;
        RECT  14.982 39.36 15.066 39.384 ;
    END
  END q[124]
  PIN q[125]
    DIRECTION OUTPUT ;
    USE SIGNAL ;
    PORT
      LAYER M4 ;
        RECT  14.982 39.648 15.066 39.672 ;
    END
  END q[125]
  PIN q[126]
    DIRECTION OUTPUT ;
    USE SIGNAL ;
    PORT
      LAYER M4 ;
        RECT  14.982 39.936 15.066 39.96 ;
    END
  END q[126]
  PIN q[127]
    DIRECTION OUTPUT ;
    USE SIGNAL ;
    PORT
      LAYER M4 ;
        RECT  14.982 40.224 15.066 40.248 ;
    END
  END q[127]
  PIN q[128]
    DIRECTION OUTPUT ;
    USE SIGNAL ;
    PORT
      LAYER M4 ;
        RECT  14.982 40.464 15.066 40.488 ;
    END
  END q[128]
  PIN q[129]
    DIRECTION OUTPUT ;
    USE SIGNAL ;
    PORT
      LAYER M4 ;
        RECT  14.982 40.752 15.066 40.776 ;
    END
  END q[129]
  PIN q[12]
    DIRECTION OUTPUT ;
    USE SIGNAL ;
    PORT
      LAYER M4 ;
        RECT  14.982 8.688 15.066 8.712 ;
    END
  END q[12]
  PIN q[130]
    DIRECTION OUTPUT ;
    USE SIGNAL ;
    PORT
      LAYER M4 ;
        RECT  14.982 41.04 15.066 41.064 ;
    END
  END q[130]
  PIN q[131]
    DIRECTION OUTPUT ;
    USE SIGNAL ;
    PORT
      LAYER M4 ;
        RECT  14.982 41.28 15.066 41.304 ;
    END
  END q[131]
  PIN q[132]
    DIRECTION OUTPUT ;
    USE SIGNAL ;
    PORT
      LAYER M4 ;
        RECT  14.982 41.568 15.066 41.592 ;
    END
  END q[132]
  PIN q[133]
    DIRECTION OUTPUT ;
    USE SIGNAL ;
    PORT
      LAYER M4 ;
        RECT  14.982 41.856 15.066 41.88 ;
    END
  END q[133]
  PIN q[134]
    DIRECTION OUTPUT ;
    USE SIGNAL ;
    PORT
      LAYER M4 ;
        RECT  14.982 42.096 15.066 42.12 ;
    END
  END q[134]
  PIN q[135]
    DIRECTION OUTPUT ;
    USE SIGNAL ;
    PORT
      LAYER M4 ;
        RECT  14.982 42.384 15.066 42.408 ;
    END
  END q[135]
  PIN q[136]
    DIRECTION OUTPUT ;
    USE SIGNAL ;
    PORT
      LAYER M4 ;
        RECT  14.982 42.672 15.066 42.696 ;
    END
  END q[136]
  PIN q[137]
    DIRECTION OUTPUT ;
    USE SIGNAL ;
    PORT
      LAYER M4 ;
        RECT  14.982 42.96 15.066 42.984 ;
    END
  END q[137]
  PIN q[138]
    DIRECTION OUTPUT ;
    USE SIGNAL ;
    PORT
      LAYER M4 ;
        RECT  14.982 43.2 15.066 43.224 ;
    END
  END q[138]
  PIN q[139]
    DIRECTION OUTPUT ;
    USE SIGNAL ;
    PORT
      LAYER M4 ;
        RECT  14.982 43.488 15.066 43.512 ;
    END
  END q[139]
  PIN q[13]
    DIRECTION OUTPUT ;
    USE SIGNAL ;
    PORT
      LAYER M4 ;
        RECT  14.982 8.928 15.066 8.952 ;
    END
  END q[13]
  PIN q[140]
    DIRECTION OUTPUT ;
    USE SIGNAL ;
    PORT
      LAYER M4 ;
        RECT  14.982 43.776 15.066 43.8 ;
    END
  END q[140]
  PIN q[141]
    DIRECTION OUTPUT ;
    USE SIGNAL ;
    PORT
      LAYER M4 ;
        RECT  14.982 44.016 15.066 44.04 ;
    END
  END q[141]
  PIN q[142]
    DIRECTION OUTPUT ;
    USE SIGNAL ;
    PORT
      LAYER M4 ;
        RECT  14.982 44.304 15.066 44.328 ;
    END
  END q[142]
  PIN q[143]
    DIRECTION OUTPUT ;
    USE SIGNAL ;
    PORT
      LAYER M4 ;
        RECT  14.982 44.592 15.066 44.616 ;
    END
  END q[143]
  PIN q[144]
    DIRECTION OUTPUT ;
    USE SIGNAL ;
    PORT
      LAYER M4 ;
        RECT  14.982 44.88 15.066 44.904 ;
    END
  END q[144]
  PIN q[145]
    DIRECTION OUTPUT ;
    USE SIGNAL ;
    PORT
      LAYER M4 ;
        RECT  14.982 45.12 15.066 45.144 ;
    END
  END q[145]
  PIN q[146]
    DIRECTION OUTPUT ;
    USE SIGNAL ;
    PORT
      LAYER M4 ;
        RECT  14.982 45.408 15.066 45.432 ;
    END
  END q[146]
  PIN q[147]
    DIRECTION OUTPUT ;
    USE SIGNAL ;
    PORT
      LAYER M4 ;
        RECT  14.982 45.696 15.066 45.72 ;
    END
  END q[147]
  PIN q[148]
    DIRECTION OUTPUT ;
    USE SIGNAL ;
    PORT
      LAYER M4 ;
        RECT  14.982 45.936 15.066 45.96 ;
    END
  END q[148]
  PIN q[149]
    DIRECTION OUTPUT ;
    USE SIGNAL ;
    PORT
      LAYER M4 ;
        RECT  14.982 46.224 15.066 46.248 ;
    END
  END q[149]
  PIN q[14]
    DIRECTION OUTPUT ;
    USE SIGNAL ;
    PORT
      LAYER M4 ;
        RECT  14.982 9.216 15.066 9.24 ;
    END
  END q[14]
  PIN q[150]
    DIRECTION OUTPUT ;
    USE SIGNAL ;
    PORT
      LAYER M4 ;
        RECT  14.982 46.512 15.066 46.536 ;
    END
  END q[150]
  PIN q[151]
    DIRECTION OUTPUT ;
    USE SIGNAL ;
    PORT
      LAYER M4 ;
        RECT  14.982 46.8 15.066 46.824 ;
    END
  END q[151]
  PIN q[152]
    DIRECTION OUTPUT ;
    USE SIGNAL ;
    PORT
      LAYER M4 ;
        RECT  14.982 47.04 15.066 47.064 ;
    END
  END q[152]
  PIN q[153]
    DIRECTION OUTPUT ;
    USE SIGNAL ;
    PORT
      LAYER M4 ;
        RECT  14.982 47.328 15.066 47.352 ;
    END
  END q[153]
  PIN q[154]
    DIRECTION OUTPUT ;
    USE SIGNAL ;
    PORT
      LAYER M4 ;
        RECT  14.982 47.616 15.066 47.64 ;
    END
  END q[154]
  PIN q[155]
    DIRECTION OUTPUT ;
    USE SIGNAL ;
    PORT
      LAYER M4 ;
        RECT  14.982 47.856 15.066 47.88 ;
    END
  END q[155]
  PIN q[156]
    DIRECTION OUTPUT ;
    USE SIGNAL ;
    PORT
      LAYER M4 ;
        RECT  14.982 48.144 15.066 48.168 ;
    END
  END q[156]
  PIN q[157]
    DIRECTION OUTPUT ;
    USE SIGNAL ;
    PORT
      LAYER M4 ;
        RECT  14.982 48.432 15.066 48.456 ;
    END
  END q[157]
  PIN q[158]
    DIRECTION OUTPUT ;
    USE SIGNAL ;
    PORT
      LAYER M4 ;
        RECT  14.982 48.72 15.066 48.744 ;
    END
  END q[158]
  PIN q[159]
    DIRECTION OUTPUT ;
    USE SIGNAL ;
    PORT
      LAYER M4 ;
        RECT  14.982 48.96 15.066 48.984 ;
    END
  END q[159]
  PIN q[15]
    DIRECTION OUTPUT ;
    USE SIGNAL ;
    PORT
      LAYER M4 ;
        RECT  14.982 9.504 15.066 9.528 ;
    END
  END q[15]
  PIN q[160]
    DIRECTION OUTPUT ;
    USE SIGNAL ;
    PORT
      LAYER M4 ;
        RECT  14.982 49.248 15.066 49.272 ;
    END
  END q[160]
  PIN q[161]
    DIRECTION OUTPUT ;
    USE SIGNAL ;
    PORT
      LAYER M4 ;
        RECT  14.982 49.536 15.066 49.56 ;
    END
  END q[161]
  PIN q[162]
    DIRECTION OUTPUT ;
    USE SIGNAL ;
    PORT
      LAYER M4 ;
        RECT  14.982 49.776 15.066 49.8 ;
    END
  END q[162]
  PIN q[163]
    DIRECTION OUTPUT ;
    USE SIGNAL ;
    PORT
      LAYER M4 ;
        RECT  14.982 50.064 15.066 50.088 ;
    END
  END q[163]
  PIN q[164]
    DIRECTION OUTPUT ;
    USE SIGNAL ;
    PORT
      LAYER M4 ;
        RECT  14.982 50.352 15.066 50.376 ;
    END
  END q[164]
  PIN q[165]
    DIRECTION OUTPUT ;
    USE SIGNAL ;
    PORT
      LAYER M4 ;
        RECT  14.982 50.64 15.066 50.664 ;
    END
  END q[165]
  PIN q[166]
    DIRECTION OUTPUT ;
    USE SIGNAL ;
    PORT
      LAYER M4 ;
        RECT  14.982 50.88 15.066 50.904 ;
    END
  END q[166]
  PIN q[167]
    DIRECTION OUTPUT ;
    USE SIGNAL ;
    PORT
      LAYER M4 ;
        RECT  14.982 51.168 15.066 51.192 ;
    END
  END q[167]
  PIN q[168]
    DIRECTION OUTPUT ;
    USE SIGNAL ;
    PORT
      LAYER M4 ;
        RECT  14.982 51.456 15.066 51.48 ;
    END
  END q[168]
  PIN q[169]
    DIRECTION OUTPUT ;
    USE SIGNAL ;
    PORT
      LAYER M4 ;
        RECT  14.982 51.696 15.066 51.72 ;
    END
  END q[169]
  PIN q[16]
    DIRECTION OUTPUT ;
    USE SIGNAL ;
    PORT
      LAYER M4 ;
        RECT  14.982 9.792 15.066 9.816 ;
    END
  END q[16]
  PIN q[170]
    DIRECTION OUTPUT ;
    USE SIGNAL ;
    PORT
      LAYER M4 ;
        RECT  14.982 51.984 15.066 52.008 ;
    END
  END q[170]
  PIN q[171]
    DIRECTION OUTPUT ;
    USE SIGNAL ;
    PORT
      LAYER M4 ;
        RECT  14.982 52.272 15.066 52.296 ;
    END
  END q[171]
  PIN q[172]
    DIRECTION OUTPUT ;
    USE SIGNAL ;
    PORT
      LAYER M4 ;
        RECT  14.982 52.512 15.066 52.536 ;
    END
  END q[172]
  PIN q[173]
    DIRECTION OUTPUT ;
    USE SIGNAL ;
    PORT
      LAYER M4 ;
        RECT  14.982 52.8 15.066 52.824 ;
    END
  END q[173]
  PIN q[174]
    DIRECTION OUTPUT ;
    USE SIGNAL ;
    PORT
      LAYER M4 ;
        RECT  14.982 53.088 15.066 53.112 ;
    END
  END q[174]
  PIN q[175]
    DIRECTION OUTPUT ;
    USE SIGNAL ;
    PORT
      LAYER M4 ;
        RECT  14.982 53.376 15.066 53.4 ;
    END
  END q[175]
  PIN q[176]
    DIRECTION OUTPUT ;
    USE SIGNAL ;
    PORT
      LAYER M4 ;
        RECT  14.982 53.616 15.066 53.64 ;
    END
  END q[176]
  PIN q[177]
    DIRECTION OUTPUT ;
    USE SIGNAL ;
    PORT
      LAYER M4 ;
        RECT  14.982 53.904 15.066 53.928 ;
    END
  END q[177]
  PIN q[178]
    DIRECTION OUTPUT ;
    USE SIGNAL ;
    PORT
      LAYER M4 ;
        RECT  14.982 54.192 15.066 54.216 ;
    END
  END q[178]
  PIN q[179]
    DIRECTION OUTPUT ;
    USE SIGNAL ;
    PORT
      LAYER M4 ;
        RECT  14.982 54.432 15.066 54.456 ;
    END
  END q[179]
  PIN q[17]
    DIRECTION OUTPUT ;
    USE SIGNAL ;
    PORT
      LAYER M4 ;
        RECT  14.982 10.032 15.066 10.056 ;
    END
  END q[17]
  PIN q[180]
    DIRECTION OUTPUT ;
    USE SIGNAL ;
    PORT
      LAYER M4 ;
        RECT  14.982 54.72 15.066 54.744 ;
    END
  END q[180]
  PIN q[181]
    DIRECTION OUTPUT ;
    USE SIGNAL ;
    PORT
      LAYER M4 ;
        RECT  14.982 55.008 15.066 55.032 ;
    END
  END q[181]
  PIN q[182]
    DIRECTION OUTPUT ;
    USE SIGNAL ;
    PORT
      LAYER M4 ;
        RECT  14.982 55.296 15.066 55.32 ;
    END
  END q[182]
  PIN q[183]
    DIRECTION OUTPUT ;
    USE SIGNAL ;
    PORT
      LAYER M4 ;
        RECT  14.982 55.536 15.066 55.56 ;
    END
  END q[183]
  PIN q[184]
    DIRECTION OUTPUT ;
    USE SIGNAL ;
    PORT
      LAYER M4 ;
        RECT  14.982 55.824 15.066 55.848 ;
    END
  END q[184]
  PIN q[185]
    DIRECTION OUTPUT ;
    USE SIGNAL ;
    PORT
      LAYER M4 ;
        RECT  14.982 56.112 15.066 56.136 ;
    END
  END q[185]
  PIN q[186]
    DIRECTION OUTPUT ;
    USE SIGNAL ;
    PORT
      LAYER M4 ;
        RECT  14.982 56.352 15.066 56.376 ;
    END
  END q[186]
  PIN q[187]
    DIRECTION OUTPUT ;
    USE SIGNAL ;
    PORT
      LAYER M4 ;
        RECT  14.982 56.64 15.066 56.664 ;
    END
  END q[187]
  PIN q[188]
    DIRECTION OUTPUT ;
    USE SIGNAL ;
    PORT
      LAYER M4 ;
        RECT  14.982 56.928 15.066 56.952 ;
    END
  END q[188]
  PIN q[189]
    DIRECTION OUTPUT ;
    USE SIGNAL ;
    PORT
      LAYER M4 ;
        RECT  14.982 57.216 15.066 57.24 ;
    END
  END q[189]
  PIN q[18]
    DIRECTION OUTPUT ;
    USE SIGNAL ;
    PORT
      LAYER M4 ;
        RECT  14.982 10.32 15.066 10.344 ;
    END
  END q[18]
  PIN q[190]
    DIRECTION OUTPUT ;
    USE SIGNAL ;
    PORT
      LAYER M4 ;
        RECT  14.982 57.456 15.066 57.48 ;
    END
  END q[190]
  PIN q[191]
    DIRECTION OUTPUT ;
    USE SIGNAL ;
    PORT
      LAYER M4 ;
        RECT  14.982 57.744 15.066 57.768 ;
    END
  END q[191]
  PIN q[192]
    DIRECTION OUTPUT ;
    USE SIGNAL ;
    PORT
      LAYER M4 ;
        RECT  14.982 58.032 15.066 58.056 ;
    END
  END q[192]
  PIN q[193]
    DIRECTION OUTPUT ;
    USE SIGNAL ;
    PORT
      LAYER M4 ;
        RECT  14.982 58.272 15.066 58.296 ;
    END
  END q[193]
  PIN q[194]
    DIRECTION OUTPUT ;
    USE SIGNAL ;
    PORT
      LAYER M4 ;
        RECT  14.982 58.56 15.066 58.584 ;
    END
  END q[194]
  PIN q[195]
    DIRECTION OUTPUT ;
    USE SIGNAL ;
    PORT
      LAYER M4 ;
        RECT  14.982 58.848 15.066 58.872 ;
    END
  END q[195]
  PIN q[196]
    DIRECTION OUTPUT ;
    USE SIGNAL ;
    PORT
      LAYER M4 ;
        RECT  14.982 59.136 15.066 59.16 ;
    END
  END q[196]
  PIN q[197]
    DIRECTION OUTPUT ;
    USE SIGNAL ;
    PORT
      LAYER M4 ;
        RECT  14.982 59.376 15.066 59.4 ;
    END
  END q[197]
  PIN q[19]
    DIRECTION OUTPUT ;
    USE SIGNAL ;
    PORT
      LAYER M4 ;
        RECT  14.982 10.608 15.066 10.632 ;
    END
  END q[19]
  PIN q[1]
    DIRECTION OUTPUT ;
    USE SIGNAL ;
    PORT
      LAYER M4 ;
        RECT  14.982 5.664 15.066 5.688 ;
    END
  END q[1]
  PIN q[20]
    DIRECTION OUTPUT ;
    USE SIGNAL ;
    PORT
      LAYER M4 ;
        RECT  14.982 10.848 15.066 10.872 ;
    END
  END q[20]
  PIN q[21]
    DIRECTION OUTPUT ;
    USE SIGNAL ;
    PORT
      LAYER M4 ;
        RECT  14.982 11.136 15.066 11.16 ;
    END
  END q[21]
  PIN q[22]
    DIRECTION OUTPUT ;
    USE SIGNAL ;
    PORT
      LAYER M4 ;
        RECT  14.982 11.424 15.066 11.448 ;
    END
  END q[22]
  PIN q[23]
    DIRECTION OUTPUT ;
    USE SIGNAL ;
    PORT
      LAYER M4 ;
        RECT  14.982 11.712 15.066 11.736 ;
    END
  END q[23]
  PIN q[24]
    DIRECTION OUTPUT ;
    USE SIGNAL ;
    PORT
      LAYER M4 ;
        RECT  14.982 11.952 15.066 11.976 ;
    END
  END q[24]
  PIN q[25]
    DIRECTION OUTPUT ;
    USE SIGNAL ;
    PORT
      LAYER M4 ;
        RECT  14.982 12.24 15.066 12.264 ;
    END
  END q[25]
  PIN q[26]
    DIRECTION OUTPUT ;
    USE SIGNAL ;
    PORT
      LAYER M4 ;
        RECT  14.982 12.528 15.066 12.552 ;
    END
  END q[26]
  PIN q[27]
    DIRECTION OUTPUT ;
    USE SIGNAL ;
    PORT
      LAYER M4 ;
        RECT  14.982 12.768 15.066 12.792 ;
    END
  END q[27]
  PIN q[28]
    DIRECTION OUTPUT ;
    USE SIGNAL ;
    PORT
      LAYER M4 ;
        RECT  14.982 13.056 15.066 13.08 ;
    END
  END q[28]
  PIN q[29]
    DIRECTION OUTPUT ;
    USE SIGNAL ;
    PORT
      LAYER M4 ;
        RECT  14.982 13.344 15.066 13.368 ;
    END
  END q[29]
  PIN q[2]
    DIRECTION OUTPUT ;
    USE SIGNAL ;
    PORT
      LAYER M4 ;
        RECT  14.982 5.952 15.066 5.976 ;
    END
  END q[2]
  PIN q[30]
    DIRECTION OUTPUT ;
    USE SIGNAL ;
    PORT
      LAYER M4 ;
        RECT  14.982 13.632 15.066 13.656 ;
    END
  END q[30]
  PIN q[31]
    DIRECTION OUTPUT ;
    USE SIGNAL ;
    PORT
      LAYER M4 ;
        RECT  14.982 13.872 15.066 13.896 ;
    END
  END q[31]
  PIN q[32]
    DIRECTION OUTPUT ;
    USE SIGNAL ;
    PORT
      LAYER M4 ;
        RECT  14.982 14.16 15.066 14.184 ;
    END
  END q[32]
  PIN q[33]
    DIRECTION OUTPUT ;
    USE SIGNAL ;
    PORT
      LAYER M4 ;
        RECT  14.982 14.448 15.066 14.472 ;
    END
  END q[33]
  PIN q[34]
    DIRECTION OUTPUT ;
    USE SIGNAL ;
    PORT
      LAYER M4 ;
        RECT  14.982 14.688 15.066 14.712 ;
    END
  END q[34]
  PIN q[35]
    DIRECTION OUTPUT ;
    USE SIGNAL ;
    PORT
      LAYER M4 ;
        RECT  14.982 14.976 15.066 15 ;
    END
  END q[35]
  PIN q[36]
    DIRECTION OUTPUT ;
    USE SIGNAL ;
    PORT
      LAYER M4 ;
        RECT  14.982 15.264 15.066 15.288 ;
    END
  END q[36]
  PIN q[37]
    DIRECTION OUTPUT ;
    USE SIGNAL ;
    PORT
      LAYER M4 ;
        RECT  14.982 15.552 15.066 15.576 ;
    END
  END q[37]
  PIN q[38]
    DIRECTION OUTPUT ;
    USE SIGNAL ;
    PORT
      LAYER M4 ;
        RECT  14.982 15.792 15.066 15.816 ;
    END
  END q[38]
  PIN q[39]
    DIRECTION OUTPUT ;
    USE SIGNAL ;
    PORT
      LAYER M4 ;
        RECT  14.982 16.08 15.066 16.104 ;
    END
  END q[39]
  PIN q[3]
    DIRECTION OUTPUT ;
    USE SIGNAL ;
    PORT
      LAYER M4 ;
        RECT  14.982 6.192 15.066 6.216 ;
    END
  END q[3]
  PIN q[40]
    DIRECTION OUTPUT ;
    USE SIGNAL ;
    PORT
      LAYER M4 ;
        RECT  14.982 16.368 15.066 16.392 ;
    END
  END q[40]
  PIN q[41]
    DIRECTION OUTPUT ;
    USE SIGNAL ;
    PORT
      LAYER M4 ;
        RECT  14.982 16.608 15.066 16.632 ;
    END
  END q[41]
  PIN q[42]
    DIRECTION OUTPUT ;
    USE SIGNAL ;
    PORT
      LAYER M4 ;
        RECT  14.982 16.896 15.066 16.92 ;
    END
  END q[42]
  PIN q[43]
    DIRECTION OUTPUT ;
    USE SIGNAL ;
    PORT
      LAYER M4 ;
        RECT  14.982 17.184 15.066 17.208 ;
    END
  END q[43]
  PIN q[44]
    DIRECTION OUTPUT ;
    USE SIGNAL ;
    PORT
      LAYER M4 ;
        RECT  14.982 17.472 15.066 17.496 ;
    END
  END q[44]
  PIN q[45]
    DIRECTION OUTPUT ;
    USE SIGNAL ;
    PORT
      LAYER M4 ;
        RECT  14.982 17.712 15.066 17.736 ;
    END
  END q[45]
  PIN q[46]
    DIRECTION OUTPUT ;
    USE SIGNAL ;
    PORT
      LAYER M4 ;
        RECT  14.982 18 15.066 18.024 ;
    END
  END q[46]
  PIN q[47]
    DIRECTION OUTPUT ;
    USE SIGNAL ;
    PORT
      LAYER M4 ;
        RECT  14.982 18.288 15.066 18.312 ;
    END
  END q[47]
  PIN q[48]
    DIRECTION OUTPUT ;
    USE SIGNAL ;
    PORT
      LAYER M4 ;
        RECT  14.982 18.528 15.066 18.552 ;
    END
  END q[48]
  PIN q[49]
    DIRECTION OUTPUT ;
    USE SIGNAL ;
    PORT
      LAYER M4 ;
        RECT  14.982 18.816 15.066 18.84 ;
    END
  END q[49]
  PIN q[4]
    DIRECTION OUTPUT ;
    USE SIGNAL ;
    PORT
      LAYER M4 ;
        RECT  14.982 6.48 15.066 6.504 ;
    END
  END q[4]
  PIN q[50]
    DIRECTION OUTPUT ;
    USE SIGNAL ;
    PORT
      LAYER M4 ;
        RECT  14.982 19.104 15.066 19.128 ;
    END
  END q[50]
  PIN q[51]
    DIRECTION OUTPUT ;
    USE SIGNAL ;
    PORT
      LAYER M4 ;
        RECT  14.982 19.344 15.066 19.368 ;
    END
  END q[51]
  PIN q[52]
    DIRECTION OUTPUT ;
    USE SIGNAL ;
    PORT
      LAYER M4 ;
        RECT  14.982 19.632 15.066 19.656 ;
    END
  END q[52]
  PIN q[53]
    DIRECTION OUTPUT ;
    USE SIGNAL ;
    PORT
      LAYER M4 ;
        RECT  14.982 19.92 15.066 19.944 ;
    END
  END q[53]
  PIN q[54]
    DIRECTION OUTPUT ;
    USE SIGNAL ;
    PORT
      LAYER M4 ;
        RECT  14.982 20.208 15.066 20.232 ;
    END
  END q[54]
  PIN q[55]
    DIRECTION OUTPUT ;
    USE SIGNAL ;
    PORT
      LAYER M4 ;
        RECT  14.982 20.448 15.066 20.472 ;
    END
  END q[55]
  PIN q[56]
    DIRECTION OUTPUT ;
    USE SIGNAL ;
    PORT
      LAYER M4 ;
        RECT  14.982 20.736 15.066 20.76 ;
    END
  END q[56]
  PIN q[57]
    DIRECTION OUTPUT ;
    USE SIGNAL ;
    PORT
      LAYER M4 ;
        RECT  14.982 21.024 15.066 21.048 ;
    END
  END q[57]
  PIN q[58]
    DIRECTION OUTPUT ;
    USE SIGNAL ;
    PORT
      LAYER M4 ;
        RECT  14.982 21.264 15.066 21.288 ;
    END
  END q[58]
  PIN q[59]
    DIRECTION OUTPUT ;
    USE SIGNAL ;
    PORT
      LAYER M4 ;
        RECT  14.982 21.552 15.066 21.576 ;
    END
  END q[59]
  PIN q[5]
    DIRECTION OUTPUT ;
    USE SIGNAL ;
    PORT
      LAYER M4 ;
        RECT  14.982 6.768 15.066 6.792 ;
    END
  END q[5]
  PIN q[60]
    DIRECTION OUTPUT ;
    USE SIGNAL ;
    PORT
      LAYER M4 ;
        RECT  14.982 21.84 15.066 21.864 ;
    END
  END q[60]
  PIN q[61]
    DIRECTION OUTPUT ;
    USE SIGNAL ;
    PORT
      LAYER M4 ;
        RECT  14.982 22.128 15.066 22.152 ;
    END
  END q[61]
  PIN q[62]
    DIRECTION OUTPUT ;
    USE SIGNAL ;
    PORT
      LAYER M4 ;
        RECT  14.982 22.368 15.066 22.392 ;
    END
  END q[62]
  PIN q[63]
    DIRECTION OUTPUT ;
    USE SIGNAL ;
    PORT
      LAYER M4 ;
        RECT  14.982 22.656 15.066 22.68 ;
    END
  END q[63]
  PIN q[64]
    DIRECTION OUTPUT ;
    USE SIGNAL ;
    PORT
      LAYER M4 ;
        RECT  14.982 22.944 15.066 22.968 ;
    END
  END q[64]
  PIN q[65]
    DIRECTION OUTPUT ;
    USE SIGNAL ;
    PORT
      LAYER M4 ;
        RECT  14.982 23.184 15.066 23.208 ;
    END
  END q[65]
  PIN q[66]
    DIRECTION OUTPUT ;
    USE SIGNAL ;
    PORT
      LAYER M4 ;
        RECT  14.982 23.472 15.066 23.496 ;
    END
  END q[66]
  PIN q[67]
    DIRECTION OUTPUT ;
    USE SIGNAL ;
    PORT
      LAYER M4 ;
        RECT  14.982 23.76 15.066 23.784 ;
    END
  END q[67]
  PIN q[68]
    DIRECTION OUTPUT ;
    USE SIGNAL ;
    PORT
      LAYER M4 ;
        RECT  14.982 24.048 15.066 24.072 ;
    END
  END q[68]
  PIN q[69]
    DIRECTION OUTPUT ;
    USE SIGNAL ;
    PORT
      LAYER M4 ;
        RECT  14.982 24.288 15.066 24.312 ;
    END
  END q[69]
  PIN q[6]
    DIRECTION OUTPUT ;
    USE SIGNAL ;
    PORT
      LAYER M4 ;
        RECT  14.982 7.056 15.066 7.08 ;
    END
  END q[6]
  PIN q[70]
    DIRECTION OUTPUT ;
    USE SIGNAL ;
    PORT
      LAYER M4 ;
        RECT  14.982 24.576 15.066 24.6 ;
    END
  END q[70]
  PIN q[71]
    DIRECTION OUTPUT ;
    USE SIGNAL ;
    PORT
      LAYER M4 ;
        RECT  14.982 24.864 15.066 24.888 ;
    END
  END q[71]
  PIN q[72]
    DIRECTION OUTPUT ;
    USE SIGNAL ;
    PORT
      LAYER M4 ;
        RECT  14.982 25.104 15.066 25.128 ;
    END
  END q[72]
  PIN q[73]
    DIRECTION OUTPUT ;
    USE SIGNAL ;
    PORT
      LAYER M4 ;
        RECT  14.982 25.392 15.066 25.416 ;
    END
  END q[73]
  PIN q[74]
    DIRECTION OUTPUT ;
    USE SIGNAL ;
    PORT
      LAYER M4 ;
        RECT  14.982 25.68 15.066 25.704 ;
    END
  END q[74]
  PIN q[75]
    DIRECTION OUTPUT ;
    USE SIGNAL ;
    PORT
      LAYER M4 ;
        RECT  14.982 25.968 15.066 25.992 ;
    END
  END q[75]
  PIN q[76]
    DIRECTION OUTPUT ;
    USE SIGNAL ;
    PORT
      LAYER M4 ;
        RECT  14.982 26.208 15.066 26.232 ;
    END
  END q[76]
  PIN q[77]
    DIRECTION OUTPUT ;
    USE SIGNAL ;
    PORT
      LAYER M4 ;
        RECT  14.982 26.496 15.066 26.52 ;
    END
  END q[77]
  PIN q[78]
    DIRECTION OUTPUT ;
    USE SIGNAL ;
    PORT
      LAYER M4 ;
        RECT  14.982 26.784 15.066 26.808 ;
    END
  END q[78]
  PIN q[79]
    DIRECTION OUTPUT ;
    USE SIGNAL ;
    PORT
      LAYER M4 ;
        RECT  14.982 27.024 15.066 27.048 ;
    END
  END q[79]
  PIN q[7]
    DIRECTION OUTPUT ;
    USE SIGNAL ;
    PORT
      LAYER M4 ;
        RECT  14.982 7.296 15.066 7.32 ;
    END
  END q[7]
  PIN q[80]
    DIRECTION OUTPUT ;
    USE SIGNAL ;
    PORT
      LAYER M4 ;
        RECT  14.982 27.312 15.066 27.336 ;
    END
  END q[80]
  PIN q[81]
    DIRECTION OUTPUT ;
    USE SIGNAL ;
    PORT
      LAYER M4 ;
        RECT  14.982 27.6 15.066 27.624 ;
    END
  END q[81]
  PIN q[82]
    DIRECTION OUTPUT ;
    USE SIGNAL ;
    PORT
      LAYER M4 ;
        RECT  14.982 27.888 15.066 27.912 ;
    END
  END q[82]
  PIN q[83]
    DIRECTION OUTPUT ;
    USE SIGNAL ;
    PORT
      LAYER M4 ;
        RECT  14.982 28.128 15.066 28.152 ;
    END
  END q[83]
  PIN q[84]
    DIRECTION OUTPUT ;
    USE SIGNAL ;
    PORT
      LAYER M4 ;
        RECT  14.982 28.416 15.066 28.44 ;
    END
  END q[84]
  PIN q[85]
    DIRECTION OUTPUT ;
    USE SIGNAL ;
    PORT
      LAYER M4 ;
        RECT  14.982 28.704 15.066 28.728 ;
    END
  END q[85]
  PIN q[86]
    DIRECTION OUTPUT ;
    USE SIGNAL ;
    PORT
      LAYER M4 ;
        RECT  14.982 28.944 15.066 28.968 ;
    END
  END q[86]
  PIN q[87]
    DIRECTION OUTPUT ;
    USE SIGNAL ;
    PORT
      LAYER M4 ;
        RECT  14.982 29.232 15.066 29.256 ;
    END
  END q[87]
  PIN q[88]
    DIRECTION OUTPUT ;
    USE SIGNAL ;
    PORT
      LAYER M4 ;
        RECT  14.982 29.52 15.066 29.544 ;
    END
  END q[88]
  PIN q[89]
    DIRECTION OUTPUT ;
    USE SIGNAL ;
    PORT
      LAYER M4 ;
        RECT  14.982 29.76 15.066 29.784 ;
    END
  END q[89]
  PIN q[8]
    DIRECTION OUTPUT ;
    USE SIGNAL ;
    PORT
      LAYER M4 ;
        RECT  14.982 7.584 15.066 7.608 ;
    END
  END q[8]
  PIN q[90]
    DIRECTION OUTPUT ;
    USE SIGNAL ;
    PORT
      LAYER M4 ;
        RECT  14.982 30.048 15.066 30.072 ;
    END
  END q[90]
  PIN q[91]
    DIRECTION OUTPUT ;
    USE SIGNAL ;
    PORT
      LAYER M4 ;
        RECT  14.982 30.336 15.066 30.36 ;
    END
  END q[91]
  PIN q[92]
    DIRECTION OUTPUT ;
    USE SIGNAL ;
    PORT
      LAYER M4 ;
        RECT  14.982 30.624 15.066 30.648 ;
    END
  END q[92]
  PIN q[93]
    DIRECTION OUTPUT ;
    USE SIGNAL ;
    PORT
      LAYER M4 ;
        RECT  14.982 30.864 15.066 30.888 ;
    END
  END q[93]
  PIN q[94]
    DIRECTION OUTPUT ;
    USE SIGNAL ;
    PORT
      LAYER M4 ;
        RECT  14.982 31.152 15.066 31.176 ;
    END
  END q[94]
  PIN q[95]
    DIRECTION OUTPUT ;
    USE SIGNAL ;
    PORT
      LAYER M4 ;
        RECT  14.982 31.44 15.066 31.464 ;
    END
  END q[95]
  PIN q[96]
    DIRECTION OUTPUT ;
    USE SIGNAL ;
    PORT
      LAYER M4 ;
        RECT  14.982 31.68 15.066 31.704 ;
    END
  END q[96]
  PIN q[97]
    DIRECTION OUTPUT ;
    USE SIGNAL ;
    PORT
      LAYER M4 ;
        RECT  14.982 31.968 15.066 31.992 ;
    END
  END q[97]
  PIN q[98]
    DIRECTION OUTPUT ;
    USE SIGNAL ;
    PORT
      LAYER M4 ;
        RECT  14.982 32.256 15.066 32.28 ;
    END
  END q[98]
  PIN q[99]
    DIRECTION OUTPUT ;
    USE SIGNAL ;
    PORT
      LAYER M4 ;
        RECT  14.982 32.544 15.066 32.568 ;
    END
  END q[99]
  PIN q[9]
    DIRECTION OUTPUT ;
    USE SIGNAL ;
    PORT
      LAYER M4 ;
        RECT  14.982 7.872 15.066 7.896 ;
    END
  END q[9]
  PIN rst_n
    DIRECTION INPUT ;
    USE SIGNAL ;
    PORT
      LAYER M5 ;
        RECT  9.696 0.054 9.72 0.138 ;
    END
    PORT
      LAYER M5 ;
        RECT  9.696 0.08 9.72 0.563 ;
    END
  END rst_n
  PIN VDD
    DIRECTION INOUT ;
    USE POWER ;
    PORT
      LAYER M5 ;
        RECT  10.692 2.151 10.812 62.649 ;
        RECT  7.992 2.151 8.112 62.649 ;
        RECT  5.292 2.151 5.412 62.649 ;
        RECT  2.592 2.151 2.712 62.649 ;
    END
  END VDD
  PIN VSS
    DIRECTION INOUT ;
    USE GROUND ;
    PORT
      LAYER M5 ;
        RECT  10.5 2.137 10.62 62.663 ;
        RECT  7.8 2.137 7.92 62.663 ;
        RECT  5.1 2.137 5.22 62.663 ;
        RECT  2.4 2.137 2.52 62.663 ;
    END
  END VSS
  # OT_OBS_CLOSED layer=M5 d_um=1.536 added=27
  OBS
    LAYER RVTN ;
     RECT  2.16 2.16 12.96 2.295 ;
     RECT  2.16 2.565 12.96 2.835 ;
     RECT  2.16 3.105 12.96 3.375 ;
     RECT  2.16 3.645 12.96 3.915 ;
     RECT  2.16 4.185 12.96 4.455 ;
     RECT  2.16 4.725 12.96 4.995 ;
     RECT  2.16 5.265 12.96 5.535 ;
     RECT  2.16 5.805 12.96 6.075 ;
     RECT  2.16 6.345 12.96 6.615 ;
     RECT  2.16 6.885 12.96 7.155 ;
     RECT  2.16 7.425 12.96 7.695 ;
     RECT  2.16 7.965 12.96 8.235 ;
     RECT  2.16 8.505 12.96 8.775 ;
     RECT  2.16 9.045 12.96 9.315 ;
     RECT  2.16 9.585 12.96 9.855 ;
     RECT  2.16 10.125 12.96 10.395 ;
     RECT  2.16 10.665 12.96 10.935 ;
     RECT  2.16 11.205 12.96 11.475 ;
     RECT  2.16 11.745 12.96 12.015 ;
     RECT  2.16 12.285 12.96 12.555 ;
     RECT  2.16 12.825 12.96 13.095 ;
     RECT  2.16 13.365 12.96 13.635 ;
     RECT  2.16 13.905 12.96 14.175 ;
     RECT  2.16 14.445 12.96 14.715 ;
     RECT  2.16 14.985 12.96 15.255 ;
     RECT  2.16 15.525 12.96 15.795 ;
     RECT  2.16 16.065 12.96 16.335 ;
     RECT  2.16 16.605 12.96 16.875 ;
     RECT  2.16 17.145 12.96 17.415 ;
     RECT  2.16 17.685 12.96 17.955 ;
     RECT  2.16 18.225 12.96 18.495 ;
     RECT  2.16 18.765 12.96 19.035 ;
     RECT  2.16 19.305 12.96 19.575 ;
     RECT  2.16 19.845 12.96 20.115 ;
     RECT  2.16 20.385 12.96 20.655 ;
     RECT  2.16 20.925 12.96 21.195 ;
     RECT  2.16 21.465 12.96 21.735 ;
     RECT  2.16 22.005 12.96 22.275 ;
     RECT  2.16 22.545 12.96 22.815 ;
     RECT  2.16 23.085 12.96 23.355 ;
     RECT  2.16 23.625 12.96 23.895 ;
     RECT  2.16 24.165 12.96 24.435 ;
     RECT  2.16 24.705 12.96 24.975 ;
     RECT  2.16 25.245 12.96 25.515 ;
     RECT  2.16 25.785 12.96 26.055 ;
     RECT  2.16 26.325 12.96 26.595 ;
     RECT  2.16 26.865 12.96 27.135 ;
     RECT  2.16 27.405 12.96 27.675 ;
     RECT  2.16 27.945 12.96 28.215 ;
     RECT  2.16 28.485 12.96 28.755 ;
     RECT  2.16 29.025 12.96 29.295 ;
     RECT  2.16 29.565 12.96 29.835 ;
     RECT  2.16 30.105 12.96 30.375 ;
     RECT  2.16 30.645 12.96 30.915 ;
     RECT  2.16 31.185 12.96 31.455 ;
     RECT  2.16 31.725 12.96 31.995 ;
     RECT  2.16 32.265 12.96 32.535 ;
     RECT  2.16 32.805 12.96 33.075 ;
     RECT  2.16 33.345 12.96 33.615 ;
     RECT  2.16 33.885 12.96 34.155 ;
     RECT  2.16 34.425 12.96 34.695 ;
     RECT  2.16 34.965 12.96 35.235 ;
     RECT  2.16 35.505 12.96 35.775 ;
     RECT  2.16 36.045 12.96 36.315 ;
     RECT  2.16 36.585 12.96 36.855 ;
     RECT  2.16 37.125 12.96 37.395 ;
     RECT  2.16 37.665 12.96 37.935 ;
     RECT  2.16 38.205 12.96 38.475 ;
     RECT  2.16 38.745 12.96 39.015 ;
     RECT  2.16 39.285 12.96 39.555 ;
     RECT  2.16 39.825 12.96 40.095 ;
     RECT  2.16 40.365 12.96 40.635 ;
     RECT  2.16 40.905 12.96 41.175 ;
     RECT  2.16 41.445 12.96 41.715 ;
     RECT  2.16 41.985 12.96 42.255 ;
     RECT  2.16 42.525 12.96 42.795 ;
     RECT  2.16 43.065 12.96 43.335 ;
     RECT  2.16 43.605 12.96 43.875 ;
     RECT  2.16 44.145 12.96 44.415 ;
     RECT  2.16 44.685 12.96 44.955 ;
     RECT  2.16 45.225 12.96 45.495 ;
     RECT  2.16 45.765 12.96 46.035 ;
     RECT  2.16 46.305 12.96 46.575 ;
     RECT  2.16 46.845 12.96 47.115 ;
     RECT  2.16 47.385 12.96 47.655 ;
     RECT  2.16 47.925 12.96 48.195 ;
     RECT  2.16 48.465 12.96 48.735 ;
     RECT  2.16 49.005 12.96 49.275 ;
     RECT  2.16 49.545 12.96 49.815 ;
     RECT  2.16 50.085 12.96 50.355 ;
     RECT  2.16 50.625 12.96 50.895 ;
     RECT  2.16 51.165 12.96 51.435 ;
     RECT  2.16 51.705 12.96 51.975 ;
     RECT  2.16 52.245 12.96 52.515 ;
     RECT  2.16 52.785 12.96 53.055 ;
     RECT  2.16 53.325 12.96 53.595 ;
     RECT  2.16 53.865 12.96 54.135 ;
     RECT  2.16 54.405 12.96 54.675 ;
     RECT  2.16 54.945 12.96 55.215 ;
     RECT  2.16 55.485 12.96 55.755 ;
     RECT  2.16 56.025 12.96 56.295 ;
     RECT  2.16 56.565 12.96 56.835 ;
     RECT  2.16 57.105 12.96 57.375 ;
     RECT  2.16 57.645 12.96 57.915 ;
     RECT  2.16 58.185 12.96 58.455 ;
     RECT  2.16 58.725 12.96 58.995 ;
     RECT  2.16 59.265 12.96 59.535 ;
     RECT  2.16 59.805 12.96 60.075 ;
     RECT  2.16 60.345 12.96 60.615 ;
     RECT  2.16 60.885 12.96 61.155 ;
     RECT  2.16 61.425 12.96 61.695 ;
     RECT  2.16 61.965 12.96 62.235 ;
     RECT  2.16 62.505 12.96 62.64 ;
    LAYER RVTP ;
     RECT  2.16 2.295 12.96 2.565 ;
     RECT  2.16 2.835 12.96 3.105 ;
     RECT  2.16 3.375 12.96 3.645 ;
     RECT  2.16 3.915 12.96 4.185 ;
     RECT  2.16 4.455 12.96 4.725 ;
     RECT  2.16 4.995 12.96 5.265 ;
     RECT  2.16 5.535 12.96 5.805 ;
     RECT  2.16 6.075 12.96 6.345 ;
     RECT  2.16 6.615 12.96 6.885 ;
     RECT  2.16 7.155 12.96 7.425 ;
     RECT  2.16 7.695 12.96 7.965 ;
     RECT  2.16 8.235 12.96 8.505 ;
     RECT  2.16 8.775 12.96 9.045 ;
     RECT  2.16 9.315 12.96 9.585 ;
     RECT  2.16 9.855 12.96 10.125 ;
     RECT  2.16 10.395 12.96 10.665 ;
     RECT  2.16 10.935 12.96 11.205 ;
     RECT  2.16 11.475 12.96 11.745 ;
     RECT  2.16 12.015 12.96 12.285 ;
     RECT  2.16 12.555 12.96 12.825 ;
     RECT  2.16 13.095 12.96 13.365 ;
     RECT  2.16 13.635 12.96 13.905 ;
     RECT  2.16 14.175 12.96 14.445 ;
     RECT  2.16 14.715 12.96 14.985 ;
     RECT  2.16 15.255 12.96 15.525 ;
     RECT  2.16 15.795 12.96 16.065 ;
     RECT  2.16 16.335 12.96 16.605 ;
     RECT  2.16 16.875 12.96 17.145 ;
     RECT  2.16 17.415 12.96 17.685 ;
     RECT  2.16 17.955 12.96 18.225 ;
     RECT  2.16 18.495 12.96 18.765 ;
     RECT  2.16 19.035 12.96 19.305 ;
     RECT  2.16 19.575 12.96 19.845 ;
     RECT  2.16 20.115 12.96 20.385 ;
     RECT  2.16 20.655 12.96 20.925 ;
     RECT  2.16 21.195 12.96 21.465 ;
     RECT  2.16 21.735 12.96 22.005 ;
     RECT  2.16 22.275 12.96 22.545 ;
     RECT  2.16 22.815 12.96 23.085 ;
     RECT  2.16 23.355 12.96 23.625 ;
     RECT  2.16 23.895 12.96 24.165 ;
     RECT  2.16 24.435 12.96 24.705 ;
     RECT  2.16 24.975 12.96 25.245 ;
     RECT  2.16 25.515 12.96 25.785 ;
     RECT  2.16 26.055 12.96 26.325 ;
     RECT  2.16 26.595 12.96 26.865 ;
     RECT  2.16 27.135 12.96 27.405 ;
     RECT  2.16 27.675 12.96 27.945 ;
     RECT  2.16 28.215 12.96 28.485 ;
     RECT  2.16 28.755 12.96 29.025 ;
     RECT  2.16 29.295 12.96 29.565 ;
     RECT  2.16 29.835 12.96 30.105 ;
     RECT  2.16 30.375 12.96 30.645 ;
     RECT  2.16 30.915 12.96 31.185 ;
     RECT  2.16 31.455 12.96 31.725 ;
     RECT  2.16 31.995 12.96 32.265 ;
     RECT  2.16 32.535 12.96 32.805 ;
     RECT  2.16 33.075 12.96 33.345 ;
     RECT  2.16 33.615 12.96 33.885 ;
     RECT  2.16 34.155 12.96 34.425 ;
     RECT  2.16 34.695 12.96 34.965 ;
     RECT  2.16 35.235 12.96 35.505 ;
     RECT  2.16 35.775 12.96 36.045 ;
     RECT  2.16 36.315 12.96 36.585 ;
     RECT  2.16 36.855 12.96 37.125 ;
     RECT  2.16 37.395 12.96 37.665 ;
     RECT  2.16 37.935 12.96 38.205 ;
     RECT  2.16 38.475 12.96 38.745 ;
     RECT  2.16 39.015 12.96 39.285 ;
     RECT  2.16 39.555 12.96 39.825 ;
     RECT  2.16 40.095 12.96 40.365 ;
     RECT  2.16 40.635 12.96 40.905 ;
     RECT  2.16 41.175 12.96 41.445 ;
     RECT  2.16 41.715 12.96 41.985 ;
     RECT  2.16 42.255 12.96 42.525 ;
     RECT  2.16 42.795 12.96 43.065 ;
     RECT  2.16 43.335 12.96 43.605 ;
     RECT  2.16 43.875 12.96 44.145 ;
     RECT  2.16 44.415 12.96 44.685 ;
     RECT  2.16 44.955 12.96 45.225 ;
     RECT  2.16 45.495 12.96 45.765 ;
     RECT  2.16 46.035 12.96 46.305 ;
     RECT  2.16 46.575 12.96 46.845 ;
     RECT  2.16 47.115 12.96 47.385 ;
     RECT  2.16 47.655 12.96 47.925 ;
     RECT  2.16 48.195 12.96 48.465 ;
     RECT  2.16 48.735 12.96 49.005 ;
     RECT  2.16 49.275 12.96 49.545 ;
     RECT  2.16 49.815 12.96 50.085 ;
     RECT  2.16 50.355 12.96 50.625 ;
     RECT  2.16 50.895 12.96 51.165 ;
     RECT  2.16 51.435 12.96 51.705 ;
     RECT  2.16 51.975 12.96 52.245 ;
     RECT  2.16 52.515 12.96 52.785 ;
     RECT  2.16 53.055 12.96 53.325 ;
     RECT  2.16 53.595 12.96 53.865 ;
     RECT  2.16 54.135 12.96 54.405 ;
     RECT  2.16 54.675 12.96 54.945 ;
     RECT  2.16 55.215 12.96 55.485 ;
     RECT  2.16 55.755 12.96 56.025 ;
     RECT  2.16 56.295 12.96 56.565 ;
     RECT  2.16 56.835 12.96 57.105 ;
     RECT  2.16 57.375 12.96 57.645 ;
     RECT  2.16 57.915 12.96 58.185 ;
     RECT  2.16 58.455 12.96 58.725 ;
     RECT  2.16 58.995 12.96 59.265 ;
     RECT  2.16 59.535 12.96 59.805 ;
     RECT  2.16 60.075 12.96 60.345 ;
     RECT  2.16 60.615 12.96 60.885 ;
     RECT  2.16 61.155 12.96 61.425 ;
     RECT  2.16 61.695 12.96 61.965 ;
     RECT  2.16 62.235 12.96 62.505 ;
    LAYER M1 ;
     RECT  2.16 2.151 12.96 62.649 ;
    LAYER M2 ;
     RECT  0.139 9.09 0.175 9.108 ;
     RECT  0.139 22.05 0.535 22.068 ;
     RECT  0.139 7.902 0.823 7.92 ;
     RECT  0.139 5.616 2.16 5.634 ;
     RECT  0.823 7.236 2.16 7.92 ;
     RECT  0.175 9.09 2.16 9.378 ;
     RECT  0.139 10.17 2.16 10.188 ;
     RECT  1.399 11.016 2.16 11.034 ;
     RECT  0.139 14.49 2.16 14.508 ;
     RECT  1.975 15.336 2.16 15.354 ;
     RECT  0.139 18.198 2.16 18.72 ;
     RECT  0.103 19.926 2.16 19.944 ;
     RECT  0.535 22.05 2.16 22.104 ;
     RECT  0.535 32.346 2.16 32.364 ;
     RECT  2.16 2.151 12.96 62.649 ;
     RECT  12.96 5.706 13.091 58.914 ;
     RECT  13.091 9.324 13.559 20.844 ;
     RECT  13.559 9.396 13.667 20.844 ;
     RECT  13.091 21.636 13.811 58.914 ;
     RECT  12.96 59.706 14.207 60.264 ;
     RECT  13.091 5.706 14.243 8.532 ;
     RECT  13.667 9.396 14.243 12.546 ;
     RECT  13.667 13.338 14.243 13.86 ;
     RECT  13.667 17.586 14.243 18.144 ;
     RECT  13.667 18.936 14.243 18.954 ;
     RECT  13.667 19.746 14.243 20.034 ;
     RECT  13.667 20.826 14.243 20.844 ;
     RECT  13.811 21.636 14.243 50.004 ;
     RECT  13.811 50.796 14.243 50.814 ;
     RECT  13.811 51.876 14.243 58.914 ;
     RECT  14.207 60.156 14.243 60.264 ;
     RECT  14.243 8.514 14.279 8.532 ;
     RECT  14.243 26.136 14.279 26.694 ;
     RECT  14.243 46.314 14.279 46.332 ;
     RECT  14.243 60.156 14.279 60.174 ;
     RECT  14.243 11.376 14.963 11.394 ;
     RECT  14.243 12.528 14.963 12.546 ;
     RECT  13.667 15.426 14.963 15.444 ;
     RECT  14.243 21.636 14.963 22.644 ;
     RECT  14.279 26.136 14.963 26.154 ;
     RECT  14.243 31.896 14.963 31.914 ;
     RECT  14.243 47.286 14.963 47.304 ;
     RECT  14.243 58.896 14.963 58.914 ;
    LAYER M3 ;
     RECT  2.415 2.143 2.505 2.413 ;
     RECT  5.115 2.143 5.205 2.413 ;
     RECT  7.815 2.143 7.905 2.413 ;
     RECT  10.515 2.143 10.605 2.413 ;
     RECT  2.415 2.413 2.697 4.765 ;
     RECT  2.415 4.765 3.006 4.801 ;
     RECT  2.415 4.801 3.294 5.035 ;
     RECT  2.415 5.035 3.474 5.161 ;
     RECT  2.376 5.161 3.474 5.305 ;
     RECT  2.34 5.305 3.474 5.341 ;
     RECT  5.115 2.413 5.397 5.341 ;
     RECT  2.304 5.341 3.474 5.539 ;
     RECT  7.815 2.413 8.097 5.539 ;
     RECT  7.704 5.539 8.097 5.575 ;
     RECT  9.648 0.523 9.666 5.575 ;
     RECT  2.304 5.539 3.762 5.611 ;
     RECT  5.115 5.341 5.49 5.611 ;
     RECT  7.164 5.575 8.097 5.611 ;
     RECT  8.928 5.575 9.666 5.611 ;
     RECT  13.644 5.419 13.662 5.659 ;
     RECT  2.304 5.611 5.49 5.701 ;
     RECT  10.515 2.413 10.797 5.737 ;
     RECT  2.304 5.701 6.03 5.765 ;
     RECT  4.788 5.765 6.03 5.881 ;
     RECT  6.84 5.611 9.666 5.881 ;
     RECT  10.515 5.737 10.818 5.881 ;
     RECT  0.144 5.611 0.162 5.933 ;
     RECT  10.44 5.881 10.818 6.043 ;
     RECT  4.788 5.881 9.666 6.151 ;
     RECT  10.44 6.043 10.854 6.151 ;
     RECT  4.788 6.151 10.854 6.269 ;
     RECT  12.06 6.115 12.078 6.305 ;
     RECT  2.304 5.765 3.798 6.421 ;
     RECT  2.268 6.421 3.798 6.461 ;
     RECT  2.304 6.461 3.798 6.511 ;
     RECT  4.788 6.269 10.797 6.511 ;
     RECT  13.644 5.659 14.238 6.809 ;
     RECT  2.304 6.511 10.797 6.845 ;
     RECT  12.276 6.421 12.294 6.845 ;
     RECT  13.068 7.231 13.086 7.325 ;
     RECT  2.304 6.845 6.75 7.483 ;
     RECT  11.988 7.231 12.078 7.591 ;
     RECT  2.268 7.483 6.75 7.655 ;
     RECT  11.988 7.591 12.618 7.691 ;
     RECT  2.304 7.655 6.75 7.727 ;
     RECT  11.988 7.691 12.078 7.889 ;
     RECT  0.828 7.231 0.846 7.897 ;
     RECT  2.34 7.727 6.75 7.933 ;
     RECT  7.815 6.845 10.797 7.933 ;
     RECT  11.772 8.005 11.79 8.041 ;
     RECT  14.22 6.809 14.238 8.107 ;
     RECT  11.664 8.041 11.79 8.159 ;
     RECT  2.34 7.933 10.797 8.195 ;
     RECT  9.648 8.195 10.797 8.203 ;
     RECT  11.664 8.159 11.718 8.203 ;
     RECT  0.144 7.897 0.846 8.333 ;
     RECT  13.644 8.107 14.238 8.429 ;
     RECT  9.648 8.203 11.718 8.537 ;
     RECT  2.34 8.195 8.874 8.539 ;
     RECT  14.256 8.509 14.274 8.717 ;
     RECT  13.068 8.923 13.086 8.969 ;
     RECT  2.304 8.539 8.874 8.977 ;
     RECT  9.648 8.537 11.646 8.977 ;
     RECT  0.828 8.333 0.846 9.085 ;
     RECT  2.304 8.977 11.646 9.319 ;
     RECT  13.536 9.211 14.238 9.347 ;
     RECT  0.144 9.085 0.846 9.389 ;
     RECT  2.304 9.319 11.862 9.419 ;
     RECT  10.515 9.419 11.862 9.617 ;
     RECT  2.304 9.419 9.738 9.689 ;
     RECT  12.24 9.661 12.258 9.815 ;
     RECT  13.644 9.347 14.238 9.821 ;
     RECT  12.6 9.931 12.618 10.085 ;
     RECT  0.18 9.389 0.846 10.156 ;
     RECT  0.144 10.156 0.846 10.445 ;
     RECT  14.22 9.821 14.238 10.597 ;
     RECT  13.644 10.597 14.238 10.637 ;
     RECT  2.415 9.689 9.738 10.651 ;
     RECT  2.304 10.651 9.738 10.705 ;
     RECT  10.515 9.617 11.43 10.705 ;
     RECT  2.304 10.705 11.43 10.895 ;
     RECT  2.304 10.895 10.854 10.967 ;
     RECT  12.168 10.705 12.186 11.003 ;
     RECT  0.828 10.445 0.846 11.011 ;
     RECT  14.22 10.637 14.238 11.371 ;
     RECT  2.304 10.967 4.266 11.435 ;
     RECT  14.22 11.371 14.958 11.453 ;
     RECT  2.412 11.435 4.266 11.713 ;
     RECT  5.076 10.967 10.854 11.713 ;
     RECT  11.988 11.371 12.006 11.713 ;
     RECT  2.412 11.713 12.006 11.749 ;
     RECT  14.22 11.453 14.238 11.821 ;
     RECT  2.412 11.749 12.618 11.849 ;
     RECT  2.412 11.849 12.546 11.975 ;
     RECT  14.184 11.821 14.238 11.981 ;
     RECT  2.412 11.975 10.89 11.984 ;
     RECT  2.412 11.984 10.797 12.209 ;
     RECT  2.412 12.209 9.738 12.217 ;
     RECT  2.304 12.217 9.738 12.245 ;
     RECT  11.988 11.975 12.402 12.245 ;
     RECT  14.22 11.981 14.238 12.281 ;
     RECT  2.304 12.245 3.978 12.317 ;
     RECT  12.348 12.245 12.402 12.515 ;
     RECT  14.94 12.523 14.958 12.56 ;
     RECT  2.304 12.317 3.942 12.659 ;
     RECT  2.304 12.659 3.762 12.797 ;
     RECT  12.348 12.515 12.366 12.893 ;
     RECT  11.988 12.991 12.258 13.289 ;
     RECT  13.644 12.721 13.662 13.333 ;
     RECT  11.988 13.289 12.006 13.361 ;
     RECT  4.752 12.245 9.738 13.441 ;
     RECT  2.304 12.797 3.33 13.531 ;
     RECT  2.304 13.531 3.87 13.639 ;
     RECT  4.608 13.441 9.738 13.639 ;
     RECT  13.644 13.333 14.238 13.901 ;
     RECT  2.304 13.639 9.738 13.945 ;
     RECT  10.515 12.209 10.797 13.945 ;
     RECT  2.304 13.945 10.797 14.207 ;
     RECT  12.024 14.179 12.042 14.215 ;
     RECT  2.304 14.207 9.738 14.369 ;
     RECT  4.716 14.369 9.738 14.405 ;
     RECT  13.644 13.901 13.662 14.443 ;
     RECT  0.828 11.011 1.422 14.485 ;
     RECT  13.572 14.443 13.662 14.549 ;
     RECT  0.144 14.485 1.422 15.149 ;
     RECT  4.716 14.405 8.91 15.187 ;
     RECT  2.304 14.369 3.762 15.295 ;
     RECT  4.5 15.187 8.91 15.295 ;
     RECT  0.828 15.149 1.422 15.331 ;
     RECT  2.304 15.295 8.91 15.331 ;
     RECT  0.828 15.331 8.91 15.389 ;
     RECT  11.736 14.215 12.042 15.449 ;
     RECT  14.94 15.259 14.958 15.449 ;
     RECT  11.808 15.449 12.042 15.485 ;
     RECT  10.515 14.207 10.797 15.565 ;
     RECT  6.552 15.389 8.91 15.691 ;
     RECT  9.72 14.405 9.738 15.691 ;
     RECT  12.024 15.485 12.042 16.025 ;
     RECT  0.828 15.389 5.778 16.303 ;
     RECT  10.515 15.565 10.854 16.501 ;
     RECT  11.916 16.411 11.934 16.501 ;
     RECT  0.828 16.303 5.814 16.537 ;
     RECT  6.552 15.691 9.738 16.537 ;
     RECT  10.515 16.501 11.934 16.835 ;
     RECT  11.736 16.835 11.934 17.041 ;
     RECT  10.515 16.835 10.854 17.105 ;
     RECT  13.644 14.549 13.662 17.339 ;
     RECT  11.736 17.041 12.042 17.375 ;
     RECT  0.828 16.537 9.738 17.519 ;
     RECT  11.736 17.375 11.934 17.725 ;
     RECT  13.068 17.467 13.086 18.029 ;
     RECT  11.52 17.725 11.934 18.149 ;
     RECT  11.916 18.149 11.934 18.185 ;
     RECT  0.828 17.519 8.766 18.193 ;
     RECT  14.22 17.581 14.238 18.523 ;
     RECT  0.144 18.193 8.766 18.571 ;
     RECT  9.72 17.519 9.738 18.571 ;
     RECT  11.988 18.571 12.258 18.725 ;
     RECT  0.144 18.571 9.738 18.769 ;
     RECT  10.515 17.105 10.797 18.769 ;
     RECT  11.988 18.725 12.006 18.995 ;
     RECT  13.644 18.523 14.238 19.099 ;
     RECT  0.144 18.769 10.797 19.133 ;
     RECT  13.068 19.099 14.238 19.229 ;
     RECT  13.644 19.229 14.238 19.499 ;
     RECT  0.828 19.133 10.797 19.507 ;
     RECT  12.24 19.615 12.258 19.741 ;
     RECT  0.828 19.507 10.926 19.805 ;
     RECT  0.828 19.805 10.854 19.921 ;
     RECT  0.108 19.921 10.854 19.949 ;
     RECT  12.24 19.741 12.582 20.075 ;
     RECT  10.515 19.949 10.854 20.417 ;
     RECT  12.168 20.389 12.186 20.425 ;
     RECT  13.068 20.203 13.086 20.443 ;
     RECT  14.22 19.499 14.238 20.443 ;
     RECT  13.068 20.443 14.238 20.579 ;
     RECT  11.736 20.425 12.186 20.615 ;
     RECT  11.736 20.615 11.754 20.623 ;
     RECT  0.108 19.949 9.558 20.695 ;
     RECT  0.108 20.695 9.702 20.849 ;
     RECT  14.22 20.579 14.238 20.849 ;
     RECT  0.108 20.849 9.558 20.885 ;
     RECT  11.592 20.623 11.754 21.029 ;
     RECT  10.515 20.417 10.797 21.469 ;
     RECT  10.515 21.469 11.286 21.811 ;
     RECT  13.068 20.579 13.086 21.929 ;
     RECT  10.515 21.811 11.43 22.351 ;
     RECT  14.94 21.547 14.958 22.441 ;
     RECT  14.256 22.441 14.958 22.513 ;
     RECT  0.108 20.885 8.766 22.549 ;
     RECT  9.54 20.885 9.558 22.549 ;
     RECT  10.515 22.351 11.466 22.621 ;
     RECT  12.348 22.585 12.618 22.621 ;
     RECT  13.644 22.513 14.958 22.685 ;
     RECT  10.515 22.621 12.618 22.783 ;
     RECT  14.22 22.685 14.958 22.973 ;
     RECT  0.108 22.549 9.558 23.017 ;
     RECT  10.515 22.783 12.834 23.017 ;
     RECT  14.22 22.973 14.274 23.501 ;
     RECT  0.108 23.017 12.834 23.789 ;
     RECT  14.22 23.501 14.238 24.331 ;
     RECT  13.68 24.331 14.238 24.605 ;
     RECT  0.108 23.789 12.618 24.629 ;
     RECT  4.824 24.629 12.618 24.781 ;
     RECT  0.108 24.629 3.834 25.555 ;
     RECT  4.824 24.781 12.726 25.555 ;
     RECT  14.22 24.605 14.238 25.709 ;
     RECT  0.108 25.555 12.726 25.745 ;
     RECT  10.368 25.745 12.726 25.979 ;
     RECT  14.94 26.131 14.958 26.237 ;
     RECT  10.515 25.979 12.726 26.519 ;
     RECT  0.108 25.745 9.558 26.789 ;
     RECT  14.22 26.491 14.274 26.813 ;
     RECT  0.108 26.789 3.978 26.825 ;
     RECT  4.86 26.789 9.558 26.905 ;
     RECT  4.86 26.905 9.594 26.941 ;
     RECT  10.515 26.519 12.294 26.941 ;
     RECT  14.22 26.813 14.238 27.019 ;
     RECT  13.644 27.019 14.238 27.059 ;
     RECT  4.86 26.941 12.294 27.445 ;
     RECT  0.108 26.825 2.697 27.595 ;
     RECT  3.888 26.825 3.978 27.595 ;
     RECT  4.86 27.445 12.402 27.599 ;
     RECT  0.108 27.595 3.978 27.715 ;
     RECT  14.22 27.059 14.238 27.841 ;
     RECT  0.108 27.715 4.122 27.869 ;
     RECT  4.86 27.599 12.078 27.869 ;
     RECT  4.86 27.869 12.042 27.905 ;
     RECT  4.86 27.905 9.27 27.913 ;
     RECT  13.644 27.841 14.238 27.917 ;
     RECT  4.788 27.913 9.27 28.049 ;
     RECT  10.044 27.905 12.042 28.409 ;
     RECT  0.108 27.869 3.906 28.795 ;
     RECT  4.824 28.049 9.27 28.795 ;
     RECT  10.08 28.409 12.042 28.859 ;
     RECT  0.108 28.795 9.27 28.949 ;
     RECT  10.08 28.859 11.754 28.985 ;
     RECT  4.752 28.949 9.27 29.021 ;
     RECT  4.86 29.021 9.27 29.405 ;
     RECT  6.624 29.405 9.27 29.605 ;
     RECT  0.108 28.949 4.014 29.875 ;
     RECT  4.86 29.405 5.814 29.875 ;
     RECT  10.26 28.985 11.754 30.145 ;
     RECT  0.108 29.875 5.814 30.181 ;
     RECT  6.624 29.605 9.414 30.181 ;
     RECT  0.108 30.181 9.414 30.677 ;
     RECT  10.26 30.145 11.79 30.721 ;
     RECT  12.6 31.081 12.618 31.181 ;
     RECT  10.188 30.721 11.79 31.261 ;
     RECT  0.108 30.677 9.27 31.801 ;
     RECT  10.188 31.261 12.006 31.801 ;
     RECT  14.22 27.917 14.238 31.891 ;
     RECT  0.108 31.801 12.006 31.955 ;
     RECT  14.22 31.891 14.958 31.997 ;
     RECT  10.404 31.955 12.006 32.161 ;
     RECT  10.404 32.161 12.618 32.261 ;
     RECT  10.404 32.261 12.186 32.459 ;
     RECT  14.22 31.997 14.238 32.539 ;
     RECT  10.404 32.459 12.006 32.729 ;
     RECT  10.404 32.729 11.682 32.881 ;
     RECT  14.184 32.539 14.238 33.067 ;
     RECT  0.108 31.955 9.27 33.389 ;
     RECT  10.008 32.881 11.682 33.511 ;
     RECT  6.624 33.389 9.27 33.547 ;
     RECT  10.008 33.511 12.078 33.547 ;
     RECT  13.644 33.067 14.238 33.611 ;
     RECT  6.624 33.547 12.078 33.655 ;
     RECT  13.788 33.611 14.238 33.989 ;
     RECT  0.108 33.389 5.814 34.159 ;
     RECT  6.624 33.655 12.402 34.159 ;
     RECT  0.108 34.159 12.402 34.195 ;
     RECT  0.108 34.195 12.654 34.205 ;
     RECT  5.004 34.205 12.654 34.349 ;
     RECT  0.108 34.205 4.266 34.385 ;
     RECT  5.115 34.349 11.934 34.691 ;
     RECT  5.115 34.691 11.754 34.889 ;
     RECT  5.115 34.889 9.45 35.179 ;
     RECT  10.515 34.889 11.754 35.231 ;
     RECT  0.108 34.385 4.086 35.311 ;
     RECT  4.824 35.179 9.45 35.311 ;
     RECT  0.108 35.311 9.45 35.699 ;
     RECT  10.515 35.231 11.682 35.851 ;
     RECT  10.08 35.851 11.682 36.211 ;
     RECT  10.08 36.211 11.754 36.311 ;
     RECT  0.108 35.699 9.27 36.517 ;
     RECT  10.08 36.311 11.682 36.517 ;
     RECT  0.108 36.517 11.682 37.291 ;
     RECT  0.108 37.291 11.754 37.319 ;
     RECT  4.068 37.319 11.754 37.355 ;
     RECT  4.464 37.355 11.754 37.391 ;
     RECT  0.108 37.319 3.294 37.613 ;
     RECT  4.464 37.391 11.646 37.625 ;
     RECT  4.5 37.625 11.646 37.931 ;
     RECT  3.42 38.245 3.438 38.281 ;
     RECT  3.42 38.281 3.726 38.399 ;
     RECT  3.528 38.399 3.726 38.471 ;
     RECT  10.26 37.931 11.646 38.515 ;
     RECT  4.5 37.931 9.126 38.677 ;
     RECT  3.96 38.677 9.126 38.821 ;
     RECT  3.96 38.821 9.27 38.947 ;
     RECT  10.26 38.515 11.682 39.181 ;
     RECT  0.108 37.613 2.697 39.211 ;
     RECT  3.96 38.947 9.45 39.211 ;
     RECT  10.26 39.181 11.754 39.281 ;
     RECT  0.108 39.211 9.45 39.289 ;
     RECT  0.108 39.289 9.486 39.479 ;
     RECT  10.26 39.281 11.682 39.479 ;
     RECT  0.108 39.479 3.114 39.515 ;
     RECT  3.888 39.479 9.486 39.749 ;
     RECT  3.888 39.749 9.414 40.127 ;
     RECT  0.108 39.515 2.697 40.267 ;
     RECT  3.888 40.127 5.454 40.267 ;
     RECT  10.26 39.479 11.574 40.405 ;
     RECT  10.26 40.405 11.646 40.441 ;
     RECT  0.108 40.267 5.454 40.595 ;
     RECT  10.152 40.441 11.646 40.675 ;
     RECT  3.852 40.595 5.454 40.873 ;
     RECT  6.228 40.127 9.414 40.873 ;
     RECT  3.852 40.873 9.414 40.981 ;
     RECT  10.152 40.675 11.682 40.981 ;
     RECT  3.852 40.981 11.682 41.071 ;
     RECT  3.852 41.071 11.754 41.207 ;
     RECT  3.852 41.207 8.874 41.369 ;
     RECT  0.108 40.595 2.898 41.371 ;
     RECT  3.852 41.369 8.766 41.371 ;
     RECT  9.72 41.207 11.754 41.909 ;
     RECT  0.108 41.371 8.766 42.235 ;
     RECT  9.72 41.909 9.738 42.235 ;
     RECT  0.108 42.235 9.738 42.287 ;
     RECT  0.108 42.287 8.946 42.449 ;
     RECT  9.72 42.287 9.738 42.629 ;
     RECT  0.108 42.449 8.766 42.719 ;
     RECT  10.515 41.909 11.754 42.719 ;
     RECT  10.515 42.719 11.682 42.989 ;
     RECT  10.515 42.989 11.574 43.141 ;
     RECT  6.588 42.719 8.766 43.333 ;
     RECT  6.588 43.333 9.054 43.373 ;
     RECT  6.588 43.373 8.946 43.529 ;
     RECT  0.108 42.719 5.814 44.221 ;
     RECT  6.588 43.529 8.766 44.221 ;
     RECT  9.864 43.141 11.574 44.311 ;
     RECT  9.72 44.311 11.574 44.419 ;
     RECT  9.72 44.419 11.754 44.581 ;
     RECT  9.72 44.581 12.078 44.725 ;
     RECT  9.72 44.725 12.618 45.115 ;
     RECT  9.72 45.115 13.086 45.329 ;
     RECT  0.108 44.221 8.766 45.689 ;
     RECT  9.72 45.329 12.474 45.869 ;
     RECT  14.22 33.989 14.238 45.931 ;
     RECT  9.756 45.869 12.474 45.995 ;
     RECT  6.12 45.689 8.766 46.237 ;
     RECT  14.22 45.931 14.274 46.337 ;
     RECT  6.12 46.237 8.91 46.535 ;
     RECT  0.108 45.689 5.397 46.777 ;
     RECT  6.12 46.535 8.766 46.777 ;
     RECT  9.756 45.995 12.114 46.805 ;
     RECT  10.26 46.805 12.114 46.877 ;
     RECT  0.108 46.777 8.766 47.281 ;
     RECT  14.22 46.337 14.238 47.281 ;
     RECT  10.26 46.877 11.646 47.309 ;
     RECT  14.22 47.281 14.958 47.357 ;
     RECT  10.296 47.309 11.646 47.695 ;
     RECT  10.296 47.695 11.682 47.849 ;
     RECT  10.332 47.849 11.682 48.119 ;
     RECT  10.515 48.119 11.682 48.775 ;
     RECT  0.108 47.281 9.378 48.929 ;
     RECT  10.515 48.775 11.754 48.973 ;
     RECT  10.26 48.973 11.754 49.081 ;
     RECT  0.108 48.929 8.91 49.199 ;
     RECT  10.26 49.081 12.042 49.199 ;
     RECT  0.108 49.199 4.374 49.235 ;
     RECT  10.26 49.199 11.754 49.351 ;
     RECT  12.564 49.315 12.582 49.469 ;
     RECT  9.792 49.351 11.754 49.981 ;
     RECT  0.108 49.235 4.122 50.009 ;
     RECT  14.22 47.357 14.238 50.009 ;
     RECT  5.115 49.199 8.91 50.089 ;
     RECT  13.644 50.053 13.806 50.093 ;
     RECT  9.792 49.981 12.294 50.395 ;
     RECT  4.824 50.089 8.91 50.431 ;
     RECT  9.792 50.395 12.402 50.431 ;
     RECT  13.788 50.093 13.806 50.791 ;
     RECT  4.824 50.431 12.402 50.819 ;
     RECT  13.788 50.791 14.238 50.909 ;
     RECT  0.108 50.009 4.014 50.935 ;
     RECT  4.824 50.819 11.466 50.935 ;
     RECT  0.108 50.935 11.466 51.089 ;
     RECT  10.26 51.089 11.466 51.359 ;
     RECT  12.384 50.819 12.402 51.475 ;
     RECT  13.788 50.909 13.806 51.539 ;
     RECT  12.384 51.475 12.474 51.629 ;
     RECT  10.515 51.359 11.466 51.745 ;
     RECT  10.515 51.745 11.97 52.169 ;
     RECT  10.515 52.169 11.754 52.205 ;
     RECT  0.108 51.089 9.306 52.411 ;
     RECT  10.515 52.205 11.682 52.591 ;
     RECT  0.108 52.411 9.45 52.709 ;
     RECT  10.188 52.591 11.682 52.861 ;
     RECT  0.108 52.709 9.378 53.555 ;
     RECT  5.04 53.555 9.378 53.941 ;
     RECT  10.116 52.861 11.682 53.941 ;
     RECT  5.04 53.941 11.682 54.175 ;
     RECT  0.108 53.555 4.122 54.331 ;
     RECT  5.04 54.175 11.754 54.401 ;
     RECT  0.108 54.331 4.266 54.481 ;
     RECT  5.04 54.401 9.414 54.481 ;
     RECT  0.108 54.481 9.414 54.869 ;
     RECT  6.66 54.869 9.414 54.941 ;
     RECT  7.815 54.941 9.414 55.139 ;
     RECT  6.66 54.941 7.074 55.211 ;
     RECT  6.696 55.211 7.074 55.409 ;
     RECT  10.224 54.401 11.754 55.795 ;
     RECT  14.22 51.691 14.238 55.819 ;
     RECT  0.108 54.869 5.886 55.831 ;
     RECT  10.224 55.795 12.294 55.831 ;
     RECT  13.644 55.819 14.238 55.949 ;
     RECT  6.732 55.409 7.074 55.957 ;
     RECT  7.815 55.139 8.766 55.957 ;
     RECT  9.9 55.831 12.294 56.065 ;
     RECT  9.9 56.065 12.366 56.219 ;
     RECT  9.9 56.219 11.682 56.641 ;
     RECT  0.108 55.831 5.958 56.731 ;
     RECT  6.732 55.957 8.766 56.731 ;
     RECT  0.108 56.731 8.766 56.768 ;
     RECT  7.815 56.768 8.766 56.875 ;
     RECT  7.815 56.875 8.946 56.911 ;
     RECT  9.792 56.641 11.682 56.911 ;
     RECT  7.815 56.911 11.682 57.001 ;
     RECT  0.108 56.768 7.074 57.065 ;
     RECT  0.108 57.065 5.742 57.101 ;
     RECT  7.815 57.001 12.186 57.181 ;
     RECT  14.22 55.949 14.238 57.211 ;
     RECT  0.108 57.101 5.562 57.335 ;
     RECT  7.815 57.181 12.582 57.371 ;
     RECT  13.644 57.211 14.238 57.407 ;
     RECT  3.564 57.335 5.562 57.569 ;
     RECT  0.108 57.335 2.697 57.581 ;
     RECT  1.404 57.581 2.697 57.821 ;
     RECT  3.564 57.569 3.582 57.875 ;
     RECT  14.22 57.407 14.238 58.027 ;
     RECT  1.98 57.821 2.697 58.109 ;
     RECT  12.636 57.991 12.654 58.145 ;
     RECT  0.108 57.581 0.126 58.219 ;
     RECT  0.036 58.219 0.126 58.253 ;
     RECT  7.815 57.371 11.646 58.261 ;
     RECT  0.036 58.253 0.054 58.349 ;
     RECT  7.815 58.261 12.582 58.379 ;
     RECT  6.732 57.065 7.074 58.495 ;
     RECT  7.815 58.379 8.73 58.495 ;
     RECT  4.356 57.569 5.397 58.531 ;
     RECT  14.22 58.027 14.958 58.555 ;
     RECT  9.792 58.379 12.582 58.649 ;
     RECT  10.515 58.649 12.582 58.685 ;
     RECT  3.96 58.531 5.397 58.693 ;
     RECT  2.415 58.109 2.697 58.699 ;
     RECT  3.96 58.693 5.49 58.699 ;
     RECT  2.415 58.699 5.49 58.843 ;
     RECT  6.444 58.495 8.73 58.919 ;
     RECT  14.184 58.555 14.958 58.919 ;
     RECT  2.304 58.843 5.49 59.071 ;
     RECT  7.092 58.919 8.442 59.189 ;
     RECT  7.092 59.189 8.097 59.225 ;
     RECT  14.184 58.919 14.274 59.371 ;
     RECT  6.336 59.035 6.354 59.459 ;
     RECT  2.304 59.071 5.562 59.495 ;
     RECT  4.356 59.495 5.562 59.575 ;
     RECT  10.515 58.685 12.294 59.575 ;
     RECT  10.515 59.575 12.474 59.611 ;
     RECT  2.415 59.495 3.546 59.729 ;
     RECT  4.356 59.575 5.706 59.729 ;
     RECT  10.515 59.611 12.582 59.729 ;
     RECT  2.415 59.729 3.222 59.765 ;
     RECT  4.356 59.729 4.374 59.765 ;
     RECT  12.24 59.729 12.582 59.881 ;
     RECT  14.148 59.371 14.274 59.999 ;
     RECT  12.24 59.881 12.618 60.035 ;
     RECT  14.22 59.999 14.274 60.179 ;
     RECT  14.22 60.179 14.238 60.269 ;
     RECT  12.564 60.035 12.582 60.305 ;
     RECT  2.415 59.765 2.697 62.387 ;
     RECT  5.115 59.729 5.397 62.387 ;
     RECT  7.815 59.225 8.097 62.387 ;
     RECT  10.515 59.729 10.797 62.387 ;
     RECT  2.415 62.387 2.505 62.657 ;
     RECT  5.115 62.387 5.205 62.657 ;
     RECT  7.815 62.387 7.905 62.657 ;
     RECT  10.515 62.387 10.605 62.657 ;
    LAYER M4 ;
     RECT  0.085 1.392 0.108 1.416 ;
     RECT  0.085 30.864 0.108 30.888 ;
     RECT  0.108 5.424 2.408 59.4 ;
     RECT  2.408 2.148 2.512 62.652 ;
     RECT  2.512 2.418 2.704 62.382 ;
     RECT  2.704 53.616 2.765 57.096 ;
     RECT  2.704 23.04 2.801 23.592 ;
     RECT  2.704 12.768 2.837 13.848 ;
     RECT  2.801 23.04 2.837 23.4 ;
     RECT  2.704 33.024 2.837 33.048 ;
     RECT  2.704 29.856 2.909 31.224 ;
     RECT  2.704 41.376 2.909 42.456 ;
     RECT  2.704 47.712 2.909 47.88 ;
     RECT  2.837 12.768 2.945 13.656 ;
     RECT  2.765 54.096 3.017 57.096 ;
     RECT  2.704 48.96 3.125 51.24 ;
     RECT  3.017 54.096 3.197 54.936 ;
     RECT  2.704 19.008 3.233 19.032 ;
     RECT  2.704 25.104 3.233 28.536 ;
     RECT  3.017 56.304 3.305 57.096 ;
     RECT  2.837 23.376 3.34 23.4 ;
     RECT  2.704 36.288 3.341 36.312 ;
     RECT  2.704 43.536 3.341 46.152 ;
     RECT  2.704 37.584 3.347 39.24 ;
     RECT  2.704 40.272 3.347 40.296 ;
     RECT  2.909 41.376 3.347 41.4 ;
     RECT  2.909 42.432 3.347 42.456 ;
     RECT  3.341 43.536 3.347 44.472 ;
     RECT  3.125 48.96 3.347 50.76 ;
     RECT  3.197 54.336 3.347 54.936 ;
     RECT  3.233 26.544 3.349 28.536 ;
     RECT  3.347 48.96 3.413 49.608 ;
     RECT  3.305 56.352 3.413 57.096 ;
     RECT  2.704 58.704 3.413 58.728 ;
     RECT  3.347 37.584 3.443 38.712 ;
     RECT  3.347 43.536 3.449 44.376 ;
     RECT  2.704 6.288 3.521 6.312 ;
     RECT  3.443 38.4 3.557 38.712 ;
     RECT  2.945 12.768 3.773 12.792 ;
     RECT  2.704 21.792 3.881 21.816 ;
     RECT  2.909 29.856 3.949 30.984 ;
     RECT  3.805 14.208 4.489 14.232 ;
     RECT  2.704 16.608 4.549 16.92 ;
     RECT  4.549 17.952 4.633 18.792 ;
     RECT  4.489 14.16 4.748 14.232 ;
     RECT  3.877 37.104 4.796 37.128 ;
     RECT  3.557 38.688 4.796 38.712 ;
     RECT  4.201 40.8 4.796 40.824 ;
     RECT  3.449 43.92 4.813 44.376 ;
     RECT  3.341 45.648 4.813 46.152 ;
     RECT  3.413 49.584 4.813 49.608 ;
     RECT  3.347 50.736 4.813 50.76 ;
     RECT  4.813 49.584 4.844 50.76 ;
     RECT  3.949 51.936 4.844 51.96 ;
     RECT  4.813 43.92 4.849 44.472 ;
     RECT  2.909 47.856 4.849 47.88 ;
     RECT  3.877 8.4 5.108 8.424 ;
     RECT  4.705 10.176 5.108 10.2 ;
     RECT  5.065 11.424 5.108 11.448 ;
     RECT  4.777 12.576 5.108 12.6 ;
     RECT  4.748 14.16 5.108 14.904 ;
     RECT  4.549 15.936 5.108 16.92 ;
     RECT  4.633 17.952 5.108 19.368 ;
     RECT  4.813 21.744 5.108 21.768 ;
     RECT  4.237 23.952 5.108 23.976 ;
     RECT  3.233 25.104 5.108 25.128 ;
     RECT  3.349 26.544 5.108 27.432 ;
     RECT  3.349 28.512 5.108 28.536 ;
     RECT  3.949 29.856 5.108 31.944 ;
     RECT  4.796 33.024 5.108 33.048 ;
     RECT  4.796 34.176 5.108 34.2 ;
     RECT  4.796 35.184 5.108 35.208 ;
     RECT  4.796 36.24 5.108 37.368 ;
     RECT  4.796 38.688 5.108 39.528 ;
     RECT  4.796 40.8 5.108 41.688 ;
     RECT  4.849 43.296 5.108 44.472 ;
     RECT  4.813 45.648 5.108 46.872 ;
     RECT  4.849 47.856 5.108 48.264 ;
     RECT  4.844 49.584 5.108 52.152 ;
     RECT  4.813 53.328 5.108 53.352 ;
     RECT  3.347 54.336 5.108 54.36 ;
     RECT  3.413 57.024 5.108 57.096 ;
     RECT  4.813 59.28 5.108 59.304 ;
     RECT  5.108 2.148 5.212 62.652 ;
     RECT  5.212 2.418 5.404 62.382 ;
     RECT  5.404 21.408 5.555 21.432 ;
     RECT  5.404 18.144 5.645 20.184 ;
     RECT  5.404 9.504 5.699 11.448 ;
     RECT  5.404 12.576 5.699 12.6 ;
     RECT  5.404 13.632 5.699 16.584 ;
     RECT  5.404 46.848 5.747 48.264 ;
     RECT  5.404 38.688 5.891 38.808 ;
     RECT  5.404 40.032 5.891 40.824 ;
     RECT  5.747 47.328 5.897 48.264 ;
     RECT  5.404 55.824 5.932 55.848 ;
     RECT  5.699 14.736 5.933 16.584 ;
     RECT  5.404 30.336 5.987 31.944 ;
     RECT  5.404 22.752 6.083 23.352 ;
     RECT  5.645 18.672 6.113 20.184 ;
     RECT  5.404 26.496 6.113 27.432 ;
     RECT  5.933 14.832 6.131 16.584 ;
     RECT  5.891 40.08 6.149 40.824 ;
     RECT  5.404 56.88 6.257 57.048 ;
     RECT  5.897 47.856 6.275 48.072 ;
     RECT  6.257 56.88 6.275 56.904 ;
     RECT  5.404 58.512 6.275 59.304 ;
     RECT  6.083 22.752 6.293 23.256 ;
     RECT  6.113 20.16 6.329 20.184 ;
     RECT  5.404 28.416 6.428 28.536 ;
     RECT  5.987 30.48 6.428 31.944 ;
     RECT  5.404 49.392 6.428 49.608 ;
     RECT  5.404 51.696 6.428 51.96 ;
     RECT  5.404 53.328 6.428 53.352 ;
     RECT  5.699 13.632 6.437 13.656 ;
     RECT  5.404 43.296 6.467 45.624 ;
     RECT  6.113 26.496 6.469 27.336 ;
     RECT  5.404 37.008 6.469 37.608 ;
     RECT  6.293 22.752 6.473 22.824 ;
     RECT  6.149 40.8 6.473 40.824 ;
     RECT  6.389 42.144 6.473 42.168 ;
     RECT  6.467 44.16 6.473 45.624 ;
     RECT  6.428 49.392 6.473 53.352 ;
     RECT  6.275 58.512 6.473 58.536 ;
     RECT  6.428 28.32 6.515 29.4 ;
     RECT  6.428 30.48 6.515 33.384 ;
     RECT  6.428 34.464 6.515 34.488 ;
     RECT  6.473 49.392 6.515 52.488 ;
     RECT  6.469 36.48 6.553 37.608 ;
     RECT  5.699 11.424 6.653 11.448 ;
     RECT  6.716 8.496 6.803 8.52 ;
     RECT  5.699 9.504 6.803 10.296 ;
     RECT  5.404 6.096 6.833 6.648 ;
     RECT  5.404 54.72 6.833 54.744 ;
     RECT  5.891 38.784 6.86 38.808 ;
     RECT  6.803 10.272 6.901 10.296 ;
     RECT  6.757 20.256 6.949 20.28 ;
     RECT  6.433 56.736 7.436 56.76 ;
     RECT  6.553 36.864 7.439 37.608 ;
     RECT  6.86 38.784 7.439 39.048 ;
     RECT  6.515 49.392 7.441 49.56 ;
     RECT  7.436 55.968 7.477 56.76 ;
     RECT  6.515 51.696 7.801 51.72 ;
     RECT  7.153 5.76 7.808 5.88 ;
     RECT  7.669 7.2 7.808 7.224 ;
     RECT  7.297 9.072 7.808 9.096 ;
     RECT  6.901 10.272 7.808 11.256 ;
     RECT  6.86 13.728 7.808 13.752 ;
     RECT  6.131 14.832 7.808 16.44 ;
     RECT  6.113 18.672 7.808 18.696 ;
     RECT  6.949 20.256 7.808 20.328 ;
     RECT  6.473 22.752 7.808 22.776 ;
     RECT  6.433 25.008 7.808 25.032 ;
     RECT  6.469 26.256 7.808 27.336 ;
     RECT  6.515 28.416 7.808 28.44 ;
     RECT  6.515 30.624 7.808 30.648 ;
     RECT  6.515 31.776 7.808 31.8 ;
     RECT  6.649 35.808 7.808 35.832 ;
     RECT  7.439 36.864 7.808 39.048 ;
     RECT  7.693 40.128 7.808 40.152 ;
     RECT  6.473 44.16 7.808 45.528 ;
     RECT  6.275 47.856 7.808 47.88 ;
     RECT  7.441 48.96 7.808 49.56 ;
     RECT  7.801 51.648 7.808 51.72 ;
     RECT  7.436 54.912 7.808 54.936 ;
     RECT  7.477 55.968 7.808 56.904 ;
     RECT  7.477 58.704 7.808 58.728 ;
     RECT  7.808 2.148 7.912 62.652 ;
     RECT  7.912 2.418 8.104 62.382 ;
     RECT  8.104 25.008 8.165 25.032 ;
     RECT  8.104 26.256 8.165 27.336 ;
     RECT  8.104 35.808 8.165 35.832 ;
     RECT  8.104 38.208 8.165 41.16 ;
     RECT  8.104 28.416 8.243 28.488 ;
     RECT  8.104 29.616 8.243 29.64 ;
     RECT  8.165 38.736 8.243 41.16 ;
     RECT  8.104 42.192 8.243 42.264 ;
     RECT  8.104 43.296 8.243 46.296 ;
     RECT  8.104 52.752 8.243 52.824 ;
     RECT  8.165 26.352 8.245 27.336 ;
     RECT  8.104 30.624 8.245 31.8 ;
     RECT  8.104 47.28 8.245 47.352 ;
     RECT  8.245 26.352 8.273 26.376 ;
     RECT  8.243 28.416 8.273 28.44 ;
     RECT  8.245 30.624 8.273 30.648 ;
     RECT  8.245 31.776 8.273 31.8 ;
     RECT  8.243 39.696 8.281 41.16 ;
     RECT  8.104 18.816 8.381 18.84 ;
     RECT  8.104 14.112 8.453 14.136 ;
     RECT  8.104 10.848 8.489 10.872 ;
     RECT  8.104 20.304 8.531 20.328 ;
     RECT  8.104 22.416 8.531 22.872 ;
     RECT  8.104 53.808 8.531 54.984 ;
     RECT  8.104 56.016 8.531 56.904 ;
     RECT  8.104 58.992 8.531 59.016 ;
     RECT  8.104 51.648 8.579 51.672 ;
     RECT  8.531 22.416 8.597 22.44 ;
     RECT  8.243 43.344 8.627 46.296 ;
     RECT  8.104 48.864 8.669 49.56 ;
     RECT  8.104 50.64 8.669 50.664 ;
     RECT  8.243 52.752 8.669 52.776 ;
     RECT  8.531 53.808 8.669 54.12 ;
     RECT  8.531 56.88 8.669 56.904 ;
     RECT  8.281 39.888 9.107 41.16 ;
     RECT  8.243 42.24 9.107 42.264 ;
     RECT  8.627 43.344 9.107 44.712 ;
     RECT  8.627 46.272 9.107 46.296 ;
     RECT  8.245 47.328 9.107 47.352 ;
     RECT  8.669 48.864 9.107 48.888 ;
     RECT  9.107 39.888 9.173 40.44 ;
     RECT  9.173 39.888 9.209 39.912 ;
     RECT  9.637 0.528 9.731 0.552 ;
     RECT  9.107 44.688 10.508 44.712 ;
     RECT  10.508 2.148 10.612 62.652 ;
     RECT  10.612 2.418 10.804 62.382 ;
     RECT  10.804 11.952 10.901 11.976 ;
     RECT  10.804 44.688 11.405 44.712 ;
     RECT  13.057 8.928 13.525 8.952 ;
     RECT  13.057 7.296 13.633 7.32 ;
     RECT  13.525 8.928 13.633 9.24 ;
     RECT  13.561 14.448 13.633 14.472 ;
     RECT  13.057 17.472 13.633 18.024 ;
     RECT  13.057 19.104 13.633 19.128 ;
     RECT  13.057 20.208 13.633 21.864 ;
     RECT  12.805 23.76 13.669 23.784 ;
     RECT  13.633 33.072 13.777 33.096 ;
     RECT  13.633 50.064 13.777 50.088 ;
     RECT  13.633 12.768 14.173 22.68 ;
     RECT  13.777 33.072 14.173 33.912 ;
     RECT  14.137 59.376 14.173 59.4 ;
     RECT  13.633 5.424 14.209 10.632 ;
     RECT  14.173 11.952 14.209 22.68 ;
     RECT  13.669 23.76 14.209 24.6 ;
     RECT  12.697 25.968 14.209 25.992 ;
     RECT  13.633 27.024 14.209 27.912 ;
     RECT  14.173 32.544 14.209 33.912 ;
     RECT  13.057 45.12 14.209 45.144 ;
     RECT  13.777 50.064 14.209 51.48 ;
     RECT  13.633 55.824 14.209 55.848 ;
     RECT  13.633 57.216 14.209 57.24 ;
     RECT  14.173 58.56 14.209 59.4 ;
     RECT  14.209 5.424 15.036 59.4 ;
    LAYER M5 ;
     RECT  0.192 1.285 0.216 1.381 ;
     RECT  0.096 1.381 0.216 1.427 ;
     RECT  2.4 2.137 2.52 2.151 ;
     RECT  5.1 2.137 5.22 2.151 ;
     RECT  7.8 2.137 7.92 2.151 ;
     RECT  10.5 2.137 10.62 2.151 ;
     RECT  7.8 2.151 8.112 5.749 ;
     RECT  7.68 5.749 8.112 6.277 ;
     RECT  0.096 1.427 0.12 6.805 ;
     RECT  0.096 6.805 0.216 7.811 ;
     RECT  5.1 2.151 5.412 10.165 ;
     RECT  6.768 6.277 8.112 10.307 ;
     RECT  5.1 10.165 5.688 14.197 ;
     RECT  4.8 14.197 5.688 14.243 ;
     RECT  4.8 14.243 5.412 14.915 ;
     RECT  5.1 14.915 5.412 15.349 ;
     RECT  6.912 10.307 8.112 15.349 ;
     RECT  5.1 15.349 8.112 15.925 ;
     RECT  4.56 15.925 8.112 16.595 ;
     RECT  4.56 16.595 5.928 18.803 ;
     RECT  4.992 18.803 5.928 19.333 ;
     RECT  6.96 16.595 8.112 19.333 ;
     RECT  4.992 19.333 8.112 20.195 ;
     RECT  6.96 20.195 8.112 20.293 ;
     RECT  6.96 20.293 8.52 20.339 ;
     RECT  4.992 20.195 5.928 21.779 ;
     RECT  2.4 2.151 2.712 21.781 ;
     RECT  7.8 20.339 8.52 22.883 ;
     RECT  5.1 21.779 5.928 23.221 ;
     RECT  5.1 23.221 5.976 23.317 ;
     RECT  2.4 21.781 3.288 23.411 ;
     RECT  2.4 23.411 2.712 26.725 ;
     RECT  5.1 23.317 6.072 26.725 ;
     RECT  4.896 26.725 6.072 27.205 ;
     RECT  7.8 22.883 8.112 27.301 ;
     RECT  4.896 27.205 6.504 27.395 ;
     RECT  2.4 26.725 3.336 27.635 ;
     RECT  2.4 27.635 2.712 30.757 ;
     RECT  0.096 7.811 0.12 30.899 ;
     RECT  2.4 30.757 2.856 30.899 ;
     RECT  7.8 27.301 8.232 31.379 ;
     RECT  5.1 27.395 6.504 33.013 ;
     RECT  7.8 31.379 8.112 35.797 ;
     RECT  4.848 33.013 6.504 36.515 ;
     RECT  2.4 30.899 2.712 37.573 ;
     RECT  4.848 36.515 6.072 37.573 ;
     RECT  7.488 35.797 8.112 37.573 ;
     RECT  2.4 37.573 3.432 38.435 ;
     RECT  4.848 37.573 8.112 38.725 ;
     RECT  4.848 38.725 8.232 38.819 ;
     RECT  6.912 38.819 8.232 40.405 ;
     RECT  4.848 38.819 5.88 40.835 ;
     RECT  4.848 40.835 5.412 41.699 ;
     RECT  6.912 40.405 9.096 42.133 ;
     RECT  6.432 42.133 9.096 43.331 ;
     RECT  6.912 43.331 9.096 44.147 ;
     RECT  2.4 38.435 3.336 44.483 ;
     RECT  6.912 44.147 8.376 44.771 ;
     RECT  7.392 44.771 8.376 45.445 ;
     RECT  5.1 41.699 5.412 45.589 ;
     RECT  7.392 45.445 8.616 46.261 ;
     RECT  7.392 46.261 9.096 47.891 ;
     RECT  5.1 45.589 5.736 48.037 ;
     RECT  7.8 47.891 9.096 48.899 ;
     RECT  2.4 44.483 2.712 48.949 ;
     RECT  5.1 48.037 6.264 49.381 ;
     RECT  5.1 49.381 6.504 49.427 ;
     RECT  5.1 49.427 5.412 50.101 ;
     RECT  2.4 48.949 3.336 50.771 ;
     RECT  4.896 50.101 5.412 52.163 ;
     RECT  6.48 49.427 6.504 52.499 ;
     RECT  5.1 52.163 5.412 53.317 ;
     RECT  7.8 48.899 8.568 53.843 ;
     RECT  5.1 53.317 5.88 54.755 ;
     RECT  2.4 50.771 2.712 54.901 ;
     RECT  7.8 53.843 8.52 54.901 ;
     RECT  5.1 54.755 5.412 55.813 ;
     RECT  5.1 55.813 5.88 56.869 ;
     RECT  2.4 54.901 3.336 58.739 ;
     RECT  7.488 54.901 8.52 58.739 ;
     RECT  7.8 58.739 8.52 59.027 ;
     RECT  5.1 56.869 6.264 59.315 ;
     RECT  2.4 58.739 2.712 62.649 ;
     RECT  5.1 59.315 5.412 62.649 ;
     RECT  7.8 59.027 8.112 62.649 ;
     RECT  10.5 2.151 10.812 62.649 ;
     RECT  2.4 62.649 2.52 62.663 ;
     RECT  5.1 62.649 5.22 62.663 ;
     RECT  7.8 62.649 7.92 62.663 ;
     RECT  10.5 62.649 10.62 62.663 ;
     RECT  5.412 6.277 6.768 10.165 ;
     RECT  5.688 10.165 6.768 10.307 ;
     RECT  5.688 10.307 6.912 14.243 ;
     RECT  5.412 14.243 6.912 15.349 ;
     RECT  4.8 14.915 5.1 15.925 ;
     RECT  5.928 16.595 6.96 19.333 ;
     RECT  5.928 20.195 6.96 20.339 ;
     RECT  6.504 27.205 7.8 35.797 ;
     RECT  6.504 35.797 7.488 36.515 ;
     RECT  6.072 36.515 7.488 37.573 ;
     RECT  3.432 37.573 4.848 38.435 ;
     RECT  3.336 38.435 4.848 41.699 ;
     RECT  5.88 38.819 6.912 40.835 ;
     RECT  9.096 40.405 10.5 44.147 ;
     RECT  5.412 40.835 6.912 42.133 ;
     RECT  5.412 42.133 6.432 43.331 ;
     RECT  5.412 43.331 6.912 44.771 ;
     RECT  8.376 44.147 8.616 45.445 ;
     RECT  5.412 44.771 5.736 45.589 ;
     RECT  9.096 46.261 10.5 48.899 ;
     RECT  7.392 47.891 7.8 48.037 ;
     RECT  6.264 48.037 7.8 49.381 ;
     RECT  6.504 49.381 7.8 52.499 ;
     RECT  5.412 49.427 6.48 52.499 ;
     RECT  5.412 52.499 5.88 53.317 ;
     RECT  5.412 54.755 5.88 55.813 ;
     RECT  6.264 56.869 7.488 58.739 ;
  END
END qwen_tx_rnen_r1
END LIBRARY
